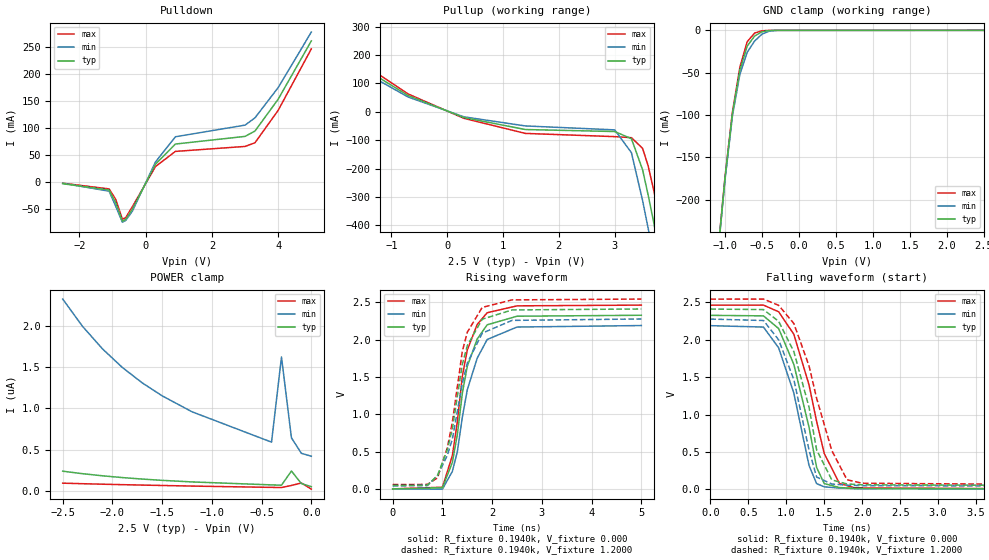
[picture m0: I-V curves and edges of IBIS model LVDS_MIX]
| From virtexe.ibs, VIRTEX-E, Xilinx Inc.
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|   Model LVDS_MIX
[Model]   LVDS_MIX
Model_type   I/O
Polarity   Non-Inverting
Enable   Active-Low
Vinh  = 1.4V
Vinl  = 1.0V
Vmeas =   1.2000V
Cref =  10.0000pF
Rref =   1.0000M
Vref =  0.000V
C_comp   5.0000pF   4.0000pF   6.0000pF
[Temperature Range]   85.0000   85.0000   85.0000
[Voltage Range]   2.5000V   2.3750V   2.6250V
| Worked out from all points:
|   slope of the pulldown table from 0 to 0.375 V, typ, clamps not added: 9.36 ohm
|   slope of the pullup table from 0 to 0.375 V, typ, clamps not added: 15.2 ohm
|   GND clamp passes 1 mA (typ) near -0.45 V on its own axis
|   rising waveform, R_fixture 0.1940k, V_fixture 0.000: 20-80 % time 389ps typ, 423ps min, 351ps max; typ from 0 V to 2.33 V
|   rising waveform, R_fixture 0.1940k, V_fixture 1.2000: 20-80 % time 417ps typ, 485ps min, 379ps max; typ from 0.048 V to 2.41 V
|   falling waveform, R_fixture 0.1940k, V_fixture 0.000: 20-80 % time 332ps typ, 319ps min, 365ps max; typ from 2.33 V to 0 V
|   falling waveform, R_fixture 0.1940k, V_fixture 1.2000: 20-80 % time 340ps typ, 332ps min, 422ps max; typ from 2.41 V to 0.048 V
[Pulldown]
| voltage   I(typ)   I(min)   I(max)
-2.5V     -3mA       -2mA       -2mA
-1.1V     -14.7mA    -16.9mA    -12.7mA
-900mV    -38.31mA   -45mA      -32.24mA
-700mV    -72.35mA   -74.44mA   -68.86mA
-600mV    -69.57mA   -71.16mA   -66.09mA
-400mV    -50.33mA   -54.17mA   -45.84mA
300mV     33.32mA    37.48mA    28.95mA
900mV     70.61mA    84.13mA    56.94mA
3V        84.79mA    105.7mA    66.17mA
3.3V      94.73mA    119.2mA    72.96mA
4V        153.8mA    175.4mA    133.2mA
5V        262mA      278.4mA    247.2mA
[Pullup]
| voltage   I(typ)   I(min)   I(max)
-2.5V     274.5mA    251.4mA    298.6mA
-700mV    57.48mA    52.2mA     62.97mA
300mV     -20.26mA   -17.68mA   -22.95mA
1.4V      -62.37mA   -49.71mA   -76.09mA
3V        -69.48mA   -63.59mA   -87.44mA
3.3V      -94.8mA    -144mA     -91.12mA
3.5V      -204.3mA   -312.7mA   -128.8mA
3.6V      -293.7mA   -410.9mA   -190.9mA
3.7V      -390.7mA   -512.3mA   -276.8mA
3.8V      -491.6mA   -615.7mA   -372.3mA
4V        -699.1mA   -826.2mA   -574.9mA
5V        -1.775A    -1.906A    -1.645A
[GND_clamp]
| voltage   I(typ)   I(min)   I(max)
-2.5V     -1.749A    -1.75A     -1.749A
-1.1V     -265.9mA   -267.2mA   -265mA
-1V       -174.2mA   -176mA     -172.9mA
-900mV    -98.19mA   -101.1mA   -96.16mA
-800mV    -47.11mA   -52.21mA   -43.56mA
-700mV    -18.56mA   -25.86mA   -13.33mA
-600mV    -6.793mA   -12.65mA   -3.234mA
-500mV    -1.657mA   -4.488mA   -550.9uA
-400mV    -239.6uA   -899.1uA   -68.76uA
-300mV    -25.6uA    -114.5uA   -6.558uA
2.5V      49.36nA    345.2nA    8.76nA
[POWER_clamp]
| voltage   I(typ)   I(min)   I(max)
-2.5V     237.1nA    2.325uA    91.79nA
-2.3V     206.5nA    1.993uA    85.16nA
-2.1V     181.1nA    1.721uA    79.1nA
-1.9V     159.5nA    1.495uA    73.57nA
-1.7V     141.4nA    1.308uA    68.39nA
-1.5V     125.8nA    1.151uA    63.62nA
-1.2V     106.8nA    957.8nA    56.46nA
-400mV    70.72nA    589.3nA    40.57nA
-300mV    66.88nA    1.623uA    38.88nA
-200mV    238.9nA    641.8nA    64.09nA
-100mV    86.32nA    454nA      93.77nA
0V        49.3nA     418.4nA    18.92nA
[Ramp]
| variable   typ   min   max
dV/dt_r   1.3968/0.3800n   1.3140/0.4175n   1.4782/0.3546n
dV/dt_f   1.4389/0.3829n   1.3728/0.3436n   1.5019/0.4619n
R_load = 0.1940k
[Rising Waveform]
R_fixture = 0.1940k
V_fixture = 0.000
| time   V(typ)   V(min)   V(max)
0s        46.06uV    676.3nV    272.9uV
1ns       15.54mV    -3.471mV   22.69mV
1.2ns     356.3mV    235.6mV    446.6mV
1.3ns     727.2mV    500.4mV    900.1mV
1.4ns     1.281V     959.5mV    1.509V
1.5ns     1.645V     1.329V     1.863V
1.7ns     2.01V      1.754V     2.205V
1.9ns     2.2V       2.003V     2.362V
2.5ns     2.315V     2.17V      2.454V
5ns       2.328V     2.19V      2.464V
[Rising Waveform]
R_fixture = 0.1940k
V_fixture = 1.2000
V_fixture_min = 1.1000
V_fixture_max = 1.3000
| time   V(typ)   V(min)   V(max)
0s        47.67mV    39.54mV    58.48mV
700ps     51.31mV    44.12mV    60.33mV
900ps     179mV      179.4mV    147.1mV
1.1ns     528.6mV    451.6mV    554.2mV
1.2ns     808.1mV    668.1mV    896mV
1.4ns     1.671V     1.417V     1.845V
1.5ns     1.921V     1.686V     2.1V
1.8ns     2.275V     2.088V     2.433V
2.4ns     2.399V     2.259V     2.534V
5ns       2.412V     2.278V     2.545V
[Falling Waveform]
R_fixture = 0.1940k
V_fixture = 0.000
| time   V(typ)   V(min)   V(max)
0s        2.328V     2.19V      2.464V
700ps     2.321V     2.171V     2.465V
900ps     2.151V     1.893V     2.376V
1.1ns     1.671V     1.286V     2.074V
1.3ns     830.5mV    317mV      1.397V
1.4ns     291.2mV    74.89mV    907.5mV
1.5ns     74.82mV    31.71mV    478.5mV
1.7ns     22.07mV    14.63mV    78.11mV
1.9ns     9.983mV    7.904mV    18.14mV
5ns       313.1uV    218.7uV    639.9uV
[Falling Waveform]
R_fixture = 0.1940k
V_fixture = 1.2000
V_fixture_min = 1.1000
V_fixture_max = 1.3000
| time   V(typ)   V(min)   V(max)
0s        2.412V     2.278V     2.545V
700ps     2.405V     2.259V     2.546V
900ps     2.248V     2V         2.462V
1.1ns     1.843V     1.468V     2.219V
1.3ns     1.098V     524mV      1.651V
1.4ns     526.6mV    162.7mV    1.217V
1.6ns     124.1mV    69.18mV    516.6mV
1.8ns     70.18mV    54.07mV    126.2mV
2ns       58.88mV    47.63mV    79.5mV
5ns       47.98mV    39.85mV    58.86mV
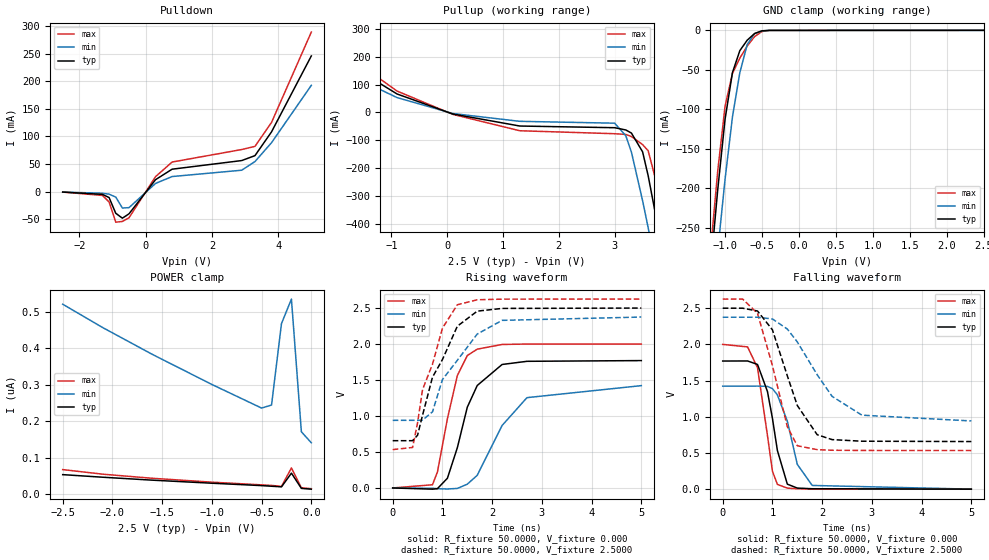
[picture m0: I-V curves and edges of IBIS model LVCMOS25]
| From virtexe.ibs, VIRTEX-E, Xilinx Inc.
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|   Model LVCMOS25
[Model]   LVCMOS25
Model_type   I/O
Polarity   Non-Inverting
Enable   Active-Low
Vinl =   0.800V
Vinh =   1.700V
Vmeas =   1.2500V
Cref =  35.0000pF
Rref =   1.0000M
Vref =  0.000V
C_comp   5.0000pF   4.0000pF   6.0000pF
[Temperature Range]   25.0000   100.0000   0.000
[Voltage Range]   2.5000V   2.3750V   2.6250V
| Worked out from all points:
|   slope of the pulldown table from 0 to 0.375 V, typ, clamps not added: 14.7 ohm
|   slope of the pullup table from 0 to 0.375 V, typ, clamps not added: 18.3 ohm
|   GND clamp passes 1 mA (typ) near -0.51 V on its own axis
|   rising waveform, R_fixture 50.0000, V_fixture 0.000: 20-80 % time 475ps typ, 726ps min, 366ps max; typ from 0 V to 1.77 V
|   rising waveform, R_fixture 50.0000, V_fixture 2.5000: 20-80 % time 601ps typ, 757ps min, 484ps max; typ from 0.657 V to 2.5 V
|   falling waveform, R_fixture 50.0000, V_fixture 0.000: 20-80 % time 280ps typ, 334ps min, 250ps max; typ from 1.77 V to 0 V
|   falling waveform, R_fixture 50.0000, V_fixture 2.5000: 20-80 % time 575ps typ, 866ps min, 429ps max; typ from 2.5 V to 0.658 V
[Pulldown]
| voltage   I(typ)   I(min)   I(max)
-2.5V     -1mA       -1mA       -1mA
-1.3V     -5.2mA     -3.1mA     -7.1mA
-1.1V     -11mA      -4.8mA     -19mA
-900mV    -39.41mA   -10.1mA    -55.57mA
-700mV    -48.31mA   -29.86mA   -54.19mA
-500mV    -40.4mA    -29.23mA   -47.55mA
300mV     21.42mA    14.64mA    26.88mA
800mV     40.44mA    27.11mA    53.39mA
2.9V      56.07mA    38.57mA    76.04mA
3.3V      64.99mA    54.26mA    81.79mA
3.8V      108.1mA    88.46mA    125.2mA
5V        245.6mA    192.3mA    288.8mA
[Pullup]
| voltage   I(typ)   I(min)   I(max)
-2.5V     264mA      205.8mA    306.3mA
-900mV    66.19mA    53.23mA    76.68mA
100mV     -5.905mA   -4.2mA     -7.259mA
1.3V      -49.08mA   -32.21mA   -66.08mA
3V        -55.16mA   -38.87mA   -76.74mA
3.2V      -63.29mA   -84.3mA    -79.31mA
3.3V      -74.42mA   -143mA     -86.88mA
3.5V      -141.8mA   -317.3mA   -115.8mA
3.6V      -227.8mA   -414.8mA   -137.9mA
3.8V      -437.8mA   -616.9mA   -292mA
4V        -661.8mA   -823.7mA   -513mA
5V        -1.826A    -1.883A    -1.708A
[GND_clamp]
| voltage   I(typ)   I(min)   I(max)
-2.5V     -1.803A    -1.736A    -1.828A
-1.2V     -306mA     -377.1mA   -282.7mA
-1.1V     -202.5mA   -280mA     -178.8mA
-1V       -112.5mA   -188.5mA   -95.98mA
-900mV    -53.49mA   -109.7mA   -54.53mA
-800mV    -25.67mA   -53.59mA   -35.13mA
-700mV    -12.44mA   -17.88mA   -19.82mA
-600mV    -3.982mA   -4.201mA   -7.865mA
-500mV    -601.5uA   -800.3uA   -1.508mA
-400mV    -51.05uA   -119.3uA   -124.3uA
2.5V      13.94nA    71.1nA     13.68nA
[POWER_clamp]
| voltage   I(typ)   I(min)   I(max)
-2.5V     53.73nA    520.7nA    67.52nA
-2.1V     46.68nA    457nA      55.06nA
-1.6V     38.59nA    383.4nA    43.77nA
-1V       30.21nA    300.8nA    33.12nA
-500mV    23.63nA    236.1nA    25.67nA
-400mV    21.94nA    244.4nA    24.16nA
-300mV    20.26nA    467.5nA    21.48nA
-200mV    57.86nA    534.8nA    72.06nA
-100mV    16.07nA    171.2nA    17.58nA
0V        13.91nA    140.9nA    15.19nA
[Ramp]
| variable   typ   min   max
dV/dt_r   1.0620/0.4714n   0.8532/0.7213n   1.2000/0.3582n
dV/dt_f   1.1053/0.5692n   0.8595/0.8591n   1.2547/0.4192n
R_load = 50.0000
[Rising Waveform]
R_fixture = 50.0000
V_fixture = 0.000
| time   V(typ)   V(min)   V(max)
0s        1.574uV    0V         1.467uV
800ps     -16.75mV   -4.734mV   44.61mV
900ps     -9.029mV   -10.48mV   223mV
1.1ns     134.9mV    -14.46mV   961.5mV
1.3ns     559.8mV    -6.614mV   1.562V
1.5ns     1.122V     52.66mV    1.84V
1.7ns     1.424V     175.5mV    1.929V
2.2ns     1.716V     868mV      1.994V
2.7ns     1.76V      1.255V     2V
5ns       1.77V      1.422V     2V
[Rising Waveform]
R_fixture = 50.0000
V_fixture = 2.5000
V_fixture_min = 2.3750
V_fixture_max = 2.6250
| time   V(typ)   V(min)   V(max)
0s        657mV      939.5mV    533.4mV
400ps     656.9mV    939.8mV    562.6mV
500ps     732.7mV    939.7mV    904.8mV
600ps     1.011V     942.6mV    1.367V
800ps     1.54V      1.058V     1.72V
1ns       1.784V     1.506V     2.22V
1.3ns     2.248V     1.774V     2.546V
1.7ns     2.457V     2.139V     2.615V
2.2ns     2.495V     2.329V     2.624V
5ns       2.5V       2.375V     2.625V
[Falling Waveform]
R_fixture = 50.0000
V_fixture = 0.000
| time   V(typ)   V(min)   V(max)
0s        1.77V      1.423V     2V
500ps     1.771V     1.423V     1.965V
700ps     1.723V     1.424V     1.678V
900ps     1.349V     1.42V      742.2mV
1ns       978.1mV    1.389V     247.6mV
1.1ns     533.6mV    1.302V     65.83mV
1.3ns     69.35mV    938.6mV    14.34mV
1.5ns     15.38mV    343.1mV    5.733mV
1.8ns     5.986mV    51.58mV    2.842mV
5ns       275.2uV    548.4uV    165.4uV
[Falling Waveform]
R_fixture = 50.0000
V_fixture = 2.5000
V_fixture_min = 2.3750
V_fixture_max = 2.6250
| time   V(typ)   V(min)   V(max)
0s        2.5V       2.375V     2.625V
400ps     2.5V       2.375V     2.626V
700ps     2.461V     2.375V     2.429V
1ns       2.201V     2.351V     1.706V
1.3ns     1.565V     2.212V     863.1mV
1.5ns     1.156V     2.034V     600.1mV
1.9ns     752.3mV    1.581V     546.1mV
2.2ns     684.7mV    1.282V     537.7mV
2.8ns     662.5mV    1.022V     534.8mV
5ns       657.8mV    942.5mV    533.8mV
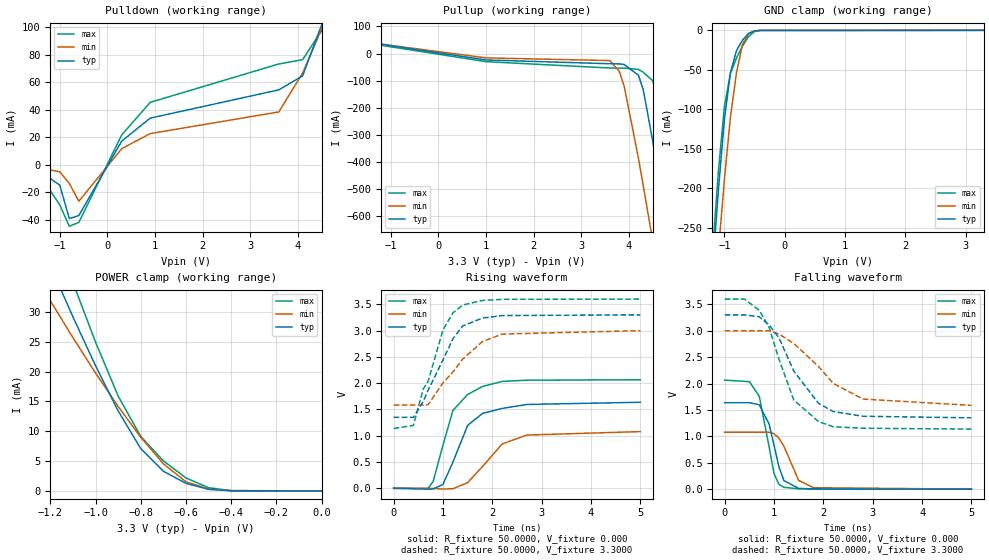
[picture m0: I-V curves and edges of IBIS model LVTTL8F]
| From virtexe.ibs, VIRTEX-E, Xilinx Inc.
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|   Model LVTTL8F
[Model]   LVTTL8F
Model_type   I/O
Polarity   Non-Inverting
Enable   Active-Low
Vinl =   0.800V
Vinh =   2.000V
Vmeas =   1.4000V
Cref =  35.0000pF
Rref =   1.0000M
Vref =  0.000V
C_comp   5.0000pF   4.0000pF   6.0000pF
[Temperature Range]   25.0000   100.0000   0.000
[Voltage Range]   3.3000V   3.0000V   3.6000V
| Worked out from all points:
|   slope of the pulldown table from 0 to 0.495 V, typ, clamps not added: 19.8 ohm
|   slope of the pullup table from 0 to 0.495 V, typ, clamps not added: 37.6 ohm
|   GND clamp passes 1 mA (typ) near -0.51 V on its own axis
|   POWER clamp passes 1 mA (typ) near -0.57 V on its own axis
|   rising waveform, R_fixture 50.0000, V_fixture 0.000: 20-80 % time 495ps typ, 625ps min, 454ps max; typ from 0 V to 1.64 V
|   rising waveform, R_fixture 50.0000, V_fixture 3.3000: 20-80 % time 610ps typ, 756ps min, 526ps max; typ from 1.35 V to 3.3 V
|   falling waveform, R_fixture 50.0000, V_fixture 0.000: 20-80 % time 268ps typ, 298ps min, 250ps max; typ from 1.64 V to 0 V
|   falling waveform, R_fixture 50.0000, V_fixture 3.3000: 20-80 % time 696ps typ, 988ps min, 566ps max; typ from 3.3 V to 1.35 V
[Pulldown]
| voltage   I(typ)   I(min)   I(max)
-3.3V     0A         -1mA       -1mA
-1.5V     -2.6mA     -1.7mA     -3.1mA
-1V       -14.7mA    -5mA       -29.02mA
-800mV    -38.95mA   -13.43mA   -44.46mA
-600mV    -36.69mA   -26.35mA   -41.68mA
300mV     17.27mA    11.77mA    21.73mA
900mV     33.93mA    22.71mA    45.37mA
3.6V      54.43mA    38.43mA    73.22mA
4.1V      64.55mA    66.63mA    76.35mA
4.5V      101.7mA    98.7mA     97.41mA
4.7V      124.3mA    116.2mA    121.3mA
6.6V      381.8mA    312.2mA    428.7mA
[Pullup]
| voltage   I(typ)   I(min)   I(max)
-3.3V     88.6mA     82.8mA     87.5mA
1V        -23.82mA   -16.13mA   -29.99mA
3.6V      -37.7mA    -26.02mA   -53.41mA
3.8V      -38.18mA   -66.39mA   -53.7mA
3.9V      -40.39mA   -120.1mA   -53.85mA
4.2V      -80.09mA   -385.5mA   -58.68mA
4.3V      -132.2mA   -485.2mA   -68.69mA
4.5V      -322.1mA   -689.5mA   -100.2mA
4.7V      -541.6mA   -897.5mA   -206mA
4.9V      -768.7mA   -1.107A    -417.4mA
5.1V      -999.4mA   -1.319A    -647.8mA
6.6V      -2.764A    -2.926A    -2.46A
[GND_clamp]
| voltage   I(typ)   I(min)   I(max)
-3.3V     -2.749A    -2.594A    -2.804A
-1.2V     -306mA     -377.1mA   -282.7mA
-1.1V     -202.5mA   -280mA     -178.8mA
-1V       -112.5mA   -188.5mA   -95.98mA
-900mV    -53.5mA    -109.7mA   -54.53mA
-800mV    -25.67mA   -53.59mA   -35.13mA
-700mV    -12.44mA   -17.88mA   -19.82mA
-600mV    -3.982mA   -4.202mA   -7.865mA
-500mV    -601.5uA   -800.3uA   -1.508mA
-400mV    -51.05uA   -119.3uA   -124.3uA
3.3V      18.74nA    3.634uA    18.92nA
[POWER_clamp]
| voltage   I(typ)   I(min)   I(max)
-3.3V     237mA      175.9mA    284.4mA
-1.3V     46.69mA    38.29mA    56.33mA
-1.2V     37.79mA    31.9mA     45.45mA
-1.1V     29.2mA     25.71mA    34.95mA
-1V       21.01mA    19.78mA    24.97mA
-900mV    13.43mA    14.17mA    15.91mA
-800mV    7.091mA    8.993mA    9.139mA
-700mV    3.305mA    4.554mA    5.052mA
-600mV    1.265mA    1.529mA    2.172mA
-500mV    263.8uA    333.6uA    531.5uA
-400mV    22.63uA    44.12uA    49.77uA
0V        18.8nA     38.36nA    22.53nA
[Ramp]
| variable   typ   min   max
dV/dt_r   0.9822/0.4911n   0.6474/0.6615n   1.2390/0.4610n
dV/dt_f   1.1694/0.6885n   0.8478/0.9605n   1.4772/0.5818n
R_load = 50.0000
[Rising Waveform]
R_fixture = 50.0000
V_fixture = 0.000
| time   V(typ)   V(min)   V(max)
0s        2.364uV    2.764uV    2.269uV
700ps     -16.3mV    -698.7uV   -272uV
800ps     -13.25mV   -4.005mV   129.4mV
1ns       74.85mV    -13.35mV   822.9mV
1.2ns     495.8mV    -8.334mV   1.48V
1.5ns     1.198V     108.3mV    1.785V
1.8ns     1.424V     414.5mV    1.938V
2.2ns     1.52V      844.5mV    2.033V
2.7ns     1.595V     1.013V     2.057V
5ns       1.637V     1.079V     2.065V
[Rising Waveform]
R_fixture = 50.0000
V_fixture = 3.3000
V_fixture_min = 3.0000
V_fixture_max = 3.6000
| time   V(typ)   V(min)   V(max)
0s        1.351V     1.585V     1.137V
400ps     1.349V     1.585V     1.197V
600ps     1.652V     1.583V     1.89V
700ps     1.871V     1.593V     2.039V
1ns       2.443V     2.006V     3.013V
1.2ns     2.843V     2.212V     3.336V
1.4ns     3.088V     2.458V     3.487V
1.8ns     3.239V     2.792V     3.573V
2.2ns     3.286V     2.934V     3.595V
5ns       3.3V       2.999V     3.6V
[Falling Waveform]
R_fixture = 50.0000
V_fixture = 0.000
| time   V(typ)   V(min)   V(max)
0s        1.637V     1.08V      2.065V
500ps     1.638V     1.08V      2.036V
700ps     1.598V     1.08V      1.762V
900ps     1.233V     1.078V     803.7mV
1ns       832.1mV    1.05V      292.3mV
1.1ns     421.6mV    966.4mV    92.28mV
1.2ns     163.9mV    814.7mV    35.1mV
1.5ns     14.58mV    164.3mV    6.546mV
1.8ns     5.759mV    28.14mV    3.148mV
5ns       304.3uV    347.7uV    258.4uV
[Falling Waveform]
R_fixture = 50.0000
V_fixture = 3.3000
V_fixture_min = 3.0000
V_fixture_max = 3.6000
| time   V(typ)   V(min)   V(max)
0s        3.3V       3V         3.6V
400ps     3.3V       3V         3.6V
700ps     3.264V     3V         3.388V
900ps     3.112V     2.998V     3.064V
1.1ns     2.865V     2.938V     2.462V
1.4ns     2.237V     2.76V      1.689V
1.9ns     1.627V     2.326V     1.28V
2.2ns     1.47V      2.003V     1.183V
2.8ns     1.381V     1.706V     1.154V
5ns       1.351V     1.587V     1.138V
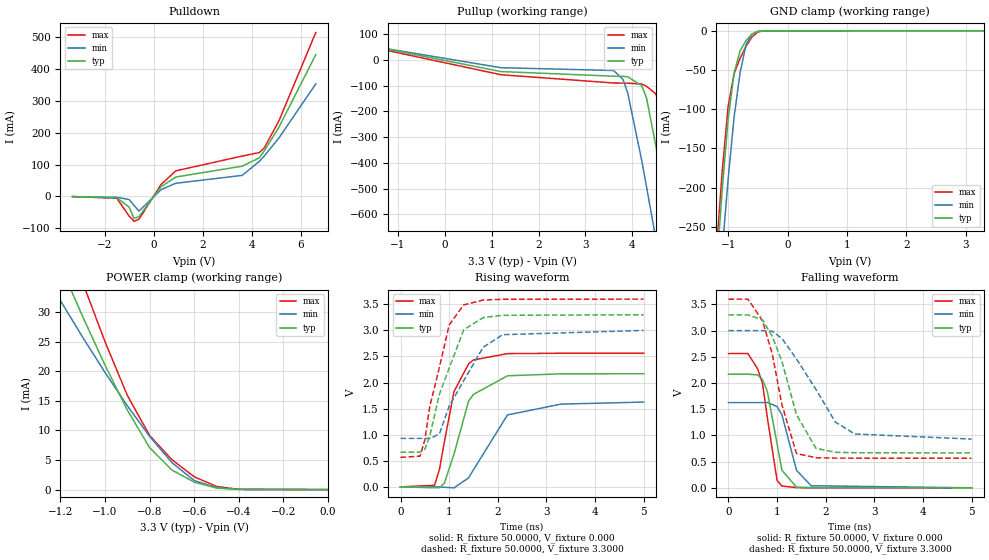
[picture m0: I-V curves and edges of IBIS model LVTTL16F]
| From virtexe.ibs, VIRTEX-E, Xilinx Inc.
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|   Model LVTTL16F
[Model]   LVTTL16F
Model_type   I/O
Polarity   Non-Inverting
Enable   Active-Low
Vinl =   0.800V
Vinh =   2.000V
Vmeas =   1.4000V
Cref =  35.0000pF
Rref =   1.0000M
Vref =  0.000V
C_comp   5.0000pF   4.0000pF   6.0000pF
[Temperature Range]   25.0000   100.0000   0.000
[Voltage Range]   3.3000V   3.0000V   3.6000V
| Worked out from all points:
|   slope of the pulldown table from 0 to 0.495 V, typ, clamps not added: 11.3 ohm
|   slope of the pullup table from 0 to 0.495 V, typ, clamps not added: 22.7 ohm
|   GND clamp passes 1 mA (typ) near -0.51 V on its own axis
|   POWER clamp passes 1 mA (typ) near -0.57 V on its own axis
|   rising waveform, R_fixture 50.0000, V_fixture 0.000: 20-80 % time 427ps typ, 615ps min, 363ps max; typ from 0 V to 2.17 V
|   rising waveform, R_fixture 50.0000, V_fixture 3.3000: 20-80 % time 515ps typ, 695ps min, 425ps max; typ from 0.665 V to 3.3 V
|   falling waveform, R_fixture 50.0000, V_fixture 0.000: 20-80 % time 257ps typ, 272ps min, 242ps max; typ from 2.17 V to 0 V
|   falling waveform, R_fixture 50.0000, V_fixture 3.3000: 20-80 % time 527ps typ, 807ps min, 422ps max; typ from 3.3 V to 0.666 V
[Pulldown]
| voltage   I(typ)   I(min)   I(max)
-3.3V     -1mA       -1mA       -1mA
-1.5V     -5mA       -3.3mA     -6.2mA
-1V       -33.9mA    -10.1mA    -62.22mA
-800mV    -70.04mA   -28.37mA   -78.77mA
-600mV    -63.86mA   -46.59mA   -72.41mA
300mV     29.85mA    20.7mA     36.95mA
900mV     60.59mA    40.95mA    80.02mA
3.6V      94.72mA    65.68mA    126.6mA
4.3V      120.9mA    109.5mA    137.7mA
4.5V      142.5mA    126.6mA    151.9mA
5.1V      217.4mA    183.5mA    237.3mA
6.6V      445.8mA    353.7mA    515.4mA
[Pullup]
| voltage   I(typ)   I(min)   I(max)
-3.3V     116.8mA    106.3mA    117.4mA
1.2V      -45.24mA   -30.27mA   -57.54mA
3.6V      -63.32mA   -41.14mA   -89.61mA
3.8V      -63.82mA   -75.74mA   -90.1mA
3.9V      -65.44mA   -127.4mA   -90.34mA
4.2V      -99.96mA   -391.3mA   -93.8mA
4.3V      -146.5mA   -490.9mA   -102.2mA
4.5V      -333.2mA   -695.1mA   -132.1mA
4.7V      -552mA     -903mA     -225.7mA
4.9V      -779mA     -1.113A    -433.5mA
5.1V      -1.009A    -1.324A    -663.2mA
6.6V      -2.775A    -2.931A    -2.475A
[GND_clamp]
| voltage   I(typ)   I(min)   I(max)
-3.3V     -2.749A    -2.594A    -2.805A
-1.2V     -306mA     -377.1mA   -282.7mA
-1.1V     -202.5mA   -280mA     -178.8mA
-1V       -112.5mA   -188.5mA   -95.98mA
-900mV    -53.5mA    -109.7mA   -54.53mA
-800mV    -25.67mA   -53.59mA   -35.13mA
-700mV    -12.44mA   -17.88mA   -19.82mA
-600mV    -3.982mA   -4.202mA   -7.866mA
-500mV    -601.5uA   -800.3uA   -1.508mA
-400mV    -51.05uA   -119.3uA   -124.5uA
3.3V      18.74nA    3.634uA    163.4nA
[POWER_clamp]
| voltage   I(typ)   I(min)   I(max)
-3.3V     237mA      175.9mA    284.4mA
-1.3V     46.69mA    38.29mA    56.33mA
-1.2V     37.79mA    31.9mA     45.45mA
-1.1V     29.2mA     25.71mA    34.95mA
-1V       21.01mA    19.78mA    24.97mA
-900mV    13.43mA    14.17mA    15.91mA
-800mV    7.091mA    8.993mA    9.139mA
-700mV    3.305mA    4.554mA    5.052mA
-600mV    1.265mA    1.529mA    2.172mA
-500mV    263.8uA    333.6uA    531.5uA
-400mV    22.63uA    44.12uA    49.77uA
0V        18.8nA     38.36nA    22.53nA
[Ramp]
| variable   typ   min   max
dV/dt_r   1.3014/0.4416n   0.9756/0.6118n   1.5372/0.3577n
dV/dt_f   1.5804/0.5476n   1.2415/0.8278n   1.8206/0.4171n
R_load = 50.0000
[Rising Waveform]
R_fixture = 50.0000
V_fixture = 0.000
| time   V(typ)   V(min)   V(max)
0s        1.652uV    1.922uV    1.601uV
700ps     -17.1mV    176.7uV    29.6mV
800ps     -17.24mV   -3.132mV   333.4mV
900ps     68.16mV    -7.704mV   854.8mV
1.1ns     629.3mV    -19.1mV    1.829V
1.4ns     1.647V     173.4mV    2.36V
1.5ns     1.773V     327.5mV    2.433V
2.2ns     2.13V      1.38V      2.555V
3.3ns     2.168V     1.587V     2.562V
5ns       2.169V     1.626V     2.562V
[Rising Waveform]
R_fixture = 50.0000
V_fixture = 3.3000
V_fixture_min = 3.0000
V_fixture_max = 3.6000
| time   V(typ)   V(min)   V(max)
0s        665.4mV    928.9mV    565.4mV
400ps     664.8mV    929.3mV    588.5mV
500ps     719.8mV    929.3mV    899.8mV
600ps     972.2mV    925.6mV    1.535V
800ps     1.776V     1.015V     2.293V
1ns       2.275V     1.547V     3.106V
1.3ns     3.013V     2.037V     3.49V
1.7ns     3.246V     2.678V     3.583V
2.1ns     3.29V      2.918V     3.597V
5ns       3.3V       3V         3.6V
[Falling Waveform]
R_fixture = 50.0000
V_fixture = 0.000
| time   V(typ)   V(min)   V(max)
0s        2.169V     1.627V     2.562V
400ps     2.169V     1.627V     2.563V
600ps     2.155V     1.627V     2.272V
700ps     2.067V     1.627V     1.992V
800ps     1.838V     1.629V     1.34V
1ns       843.3mV    1.552V     142.1mV
1.1ns     334.9mV    1.393V     35.03mV
1.4ns     13.5mV     335.1mV    4.991mV
1.7ns     4.548mV    40.84mV    2.221mV
5ns       129.4uV    363.8uV    191.5uV
[Falling Waveform]
R_fixture = 50.0000
V_fixture = 3.3000
V_fixture_min = 3.0000
V_fixture_max = 3.6000
| time   V(typ)   V(min)   V(max)
0s        3.3V       3V         3.6V
400ps     3.3V       3V         3.601V
700ps     3.206V     3V         3.192V
900ps     2.893V     2.989V     2.558V
1.1ns     2.414V     2.851V     1.584V
1.4ns     1.394V     2.458V     654mV
1.8ns     754.5mV    1.877V     575.5mV
2.2ns     678.8mV    1.254V     567.8mV
2.6ns     670.3mV    1.028V     566.6mV
5ns       666mV      930.8mV    565.7mV
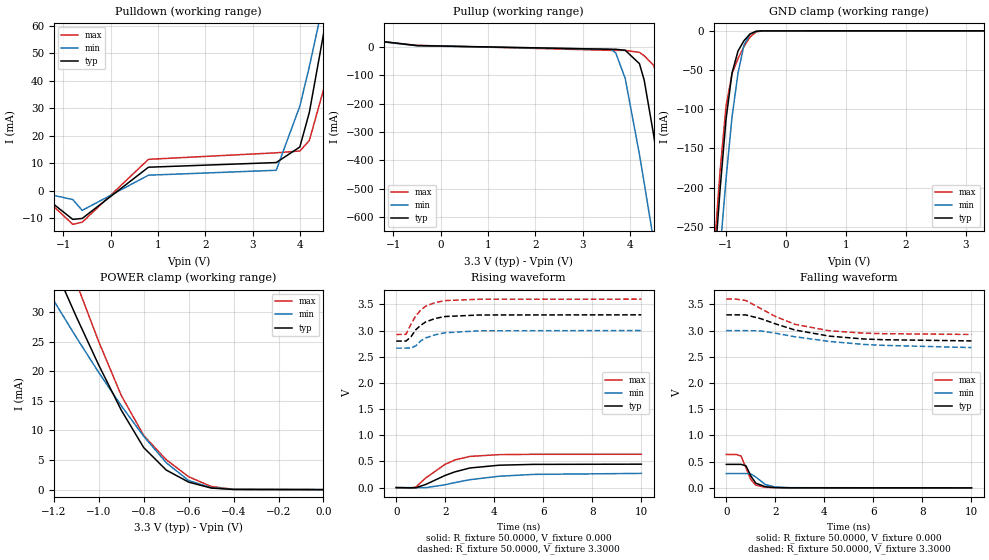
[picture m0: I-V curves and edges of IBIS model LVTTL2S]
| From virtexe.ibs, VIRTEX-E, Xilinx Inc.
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|   Model LVTTL2S
[Model]   LVTTL2S
Model_type   I/O
Polarity   Non-Inverting
Enable   Active-Low
Vinl =   0.800V
Vinh =   2.000V
Vmeas =   1.4000V
Cref =  35.0000pF
Rref =   1.0000M
Vref =  0.000V
C_comp   5.0000pF   4.0000pF   6.0000pF
[Temperature Range]   25.0000   100.0000   0.000
[Voltage Range]   3.3000V   3.0000V   3.6000V
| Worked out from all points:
|   slope of the pulldown table from 0 to 0.495 V, typ, clamps not added: 72.6 ohm
|   slope of the pullup table from 0 to 0.495 V, typ, clamps not added: 152 ohm
|   GND clamp passes 1 mA (typ) near -0.51 V on its own axis
|   POWER clamp passes 1 mA (typ) near -0.57 V on its own axis
|   rising waveform, R_fixture 50.0000, V_fixture 0.000: 20-80 % time 1.47ns typ, 2.2ns min, 1.21ns max; typ from 0 V to 0.448 V
|   rising waveform, R_fixture 50.0000, V_fixture 3.3000: 20-80 % time 780ps typ, 869ps min, 660ps max; typ from 2.8 V to 3.3 V
|   falling waveform, R_fixture 50.0000, V_fixture 0.000: 20-80 % time 339ps typ, 483ps min, 370ps max; typ from 0.448 V to 0 V
|   falling waveform, R_fixture 50.0000, V_fixture 3.3000: 20-80 % time 2.53ns typ, 3.31ns min, 2.17ns max; typ from 3.3 V to 2.8 V
[Pulldown]
| voltage   I(typ)   I(min)   I(max)
-3.3V     0A         0A         0A
-1.5V     -800uA     -500uA     -900uA
-800mV    -10.37mA   -3.16mA    -12.15mA
-600mV    -10.03mA   -7.098mA   -11.4mA
800mV     8.599mA    5.7mA      11.47mA
3.5V      10.29mA    7.484mA    13.84mA
4V        15.95mA    30.8mA     14.5mA
4.2V      28.48mA    45.11mA    18.27mA
4.5V      56.99mA    68.77mA    36.77mA
4.7V      78.21mA    85.56mA    59.04mA
4.9V      100.4mA    103mA      84.05mA
6.6V      305.2mA    264.8mA    320.6mA
[Pullup]
| voltage   I(typ)   I(min)   I(max)
-3.3V     57.9mA     57mA       55.1mA
-500mV    3.885mA    3.023mA    4.653mA
3.6V      -9.158mA   -9.435mA   -13.01mA
3.7V      -9.22mA    -22.12mA   -13.04mA
3.9V      -12.77mA   -112.2mA   -13.12mA
4.2V      -59.66mA   -379.1mA   -20.13mA
4.3V      -117.2mA   -478.9mA   -31.66mA
4.5V      -309.9mA   -683.4mA   -65.4mA
4.7V      -530mA     -891.4mA   -185.2mA
4.9V      -757.3mA   -1.101A    -399.7mA
5.1V      -988.1mA   -1.313A    -630.8mA
6.6V      -2.753A    -2.919A    -2.443A
[GND_clamp]
| voltage   I(typ)   I(min)   I(max)
-3.3V     -2.749A    -2.594A    -2.804A
-1.2V     -306mA     -377.1mA   -282.7mA
-1.1V     -202.5mA   -280mA     -178.8mA
-1V       -112.5mA   -188.5mA   -95.98mA
-900mV    -53.5mA    -109.7mA   -54.53mA
-800mV    -25.67mA   -53.59mA   -35.13mA
-700mV    -12.44mA   -17.88mA   -19.82mA
-600mV    -3.982mA   -4.202mA   -7.865mA
-500mV    -601.5uA   -800.3uA   -1.508mA
-400mV    -51.05uA   -119.3uA   -124.3uA
3.3V      18.74nA    3.634uA    18.92nA
[POWER_clamp]
| voltage   I(typ)   I(min)   I(max)
-3.3V     237mA      175.9mA    284.4mA
-1.3V     46.69mA    38.29mA    56.33mA
-1.2V     37.79mA    31.9mA     45.45mA
-1.1V     29.2mA     25.71mA    34.95mA
-1V       21.01mA    19.78mA    24.97mA
-900mV    13.43mA    14.17mA    15.91mA
-800mV    7.091mA    8.993mA    9.139mA
-700mV    3.305mA    4.554mA    5.052mA
-600mV    1.265mA    1.529mA    2.172mA
-500mV    263.8uA    333.6uA    531.5uA
-400mV    22.63uA    44.12uA    49.77uA
0V        18.8nA     38.3nA     22.53nA
[Ramp]
| variable   typ   min   max
dV/dt_r   0.2686/1.5061n   0.1628/2.2520n   0.3821/1.1512n
dV/dt_f   0.2982/2.5459n   0.1944/3.3756n   0.4044/2.1209n
R_load = 50.0000
[Rising Waveform]
R_fixture = 50.0000
V_fixture = 0.000
| time   V(typ)   V(min)   V(max)
0s        4.623uV    5.001uV    4.595uV
600ps     -4.323mV   -213.2uV   -5.002mV
800ps     -3.202mV   -2.826mV   10.53mV
1.2ns     59.38mV    -1.959mV   182.3mV
2ns       233.4mV    54.73mV    446.3mV
2.4ns     301.3mV    96.4mV     528.6mV
3ns       374.1mV    150.5mV    595.6mV
4.2ns     427.9mV    217.1mV    629.8mV
5.6ns     443.5mV    252.2mV    635.9mV
10ns      447.7mV    271.4mV    636.8mV
[Rising Waveform]
R_fixture = 50.0000
V_fixture = 3.3000
V_fixture_min = 3.0000
V_fixture_max = 3.6000
| time   V(typ)   V(min)   V(max)
0s        2.799V     2.664V     2.925V
400ps     2.799V     2.664V     2.928V
600ps     2.88V      2.667V     3.121V
800ps     3.016V     2.708V     3.283V
1ns       3.1V       2.803V     3.39V
1.2ns     3.164V     2.86V      3.466V
1.6ns     3.232V     2.92V      3.535V
2ns       3.268V     2.958V     3.572V
3.4ns     3.297V     2.995V     3.598V
10ns      3.3V       3V         3.6V
[Falling Waveform]
R_fixture = 50.0000
V_fixture = 0.000
| time   V(typ)   V(min)   V(max)
0s        447.8mV    272.6mV    636.8mV
400ps     447.8mV    272.6mV    636.9mV
600ps     447.9mV    272.6mV    607.8mV
800ps     420.5mV    272.8mV    382.4mV
1ns       226.1mV    266.6mV    157.7mV
1.2ns     90.23mV    205.9mV    51.77mV
1.6ns     20.52mV    61.28mV    9.863mV
2ns       4.827mV    15.28mV    2.716mV
2.6ns     1.226mV    3.226mV    740.4uV
10ns      24.85uV    50.11uV    26.57uV
[Falling Waveform]
R_fixture = 50.0000
V_fixture = 3.3000
V_fixture_min = 3.0000
V_fixture_max = 3.6000
| time   V(typ)   V(min)   V(max)
0s        3.3V       3V         3.6V
400ps     3.3V       3V         3.6V
800ps     3.298V     3V         3.574V
1.4ns     3.228V     2.994V     3.421V
2ns       3.129V     2.95V      3.269V
2.8ns     3.011V     2.882V     3.119V
4.2ns     2.894V     2.793V     2.997V
5.6ns     2.84V      2.736V     2.951V
6.4ns     2.826V     2.718V     2.941V
10ns      2.803V     2.676V     2.926V
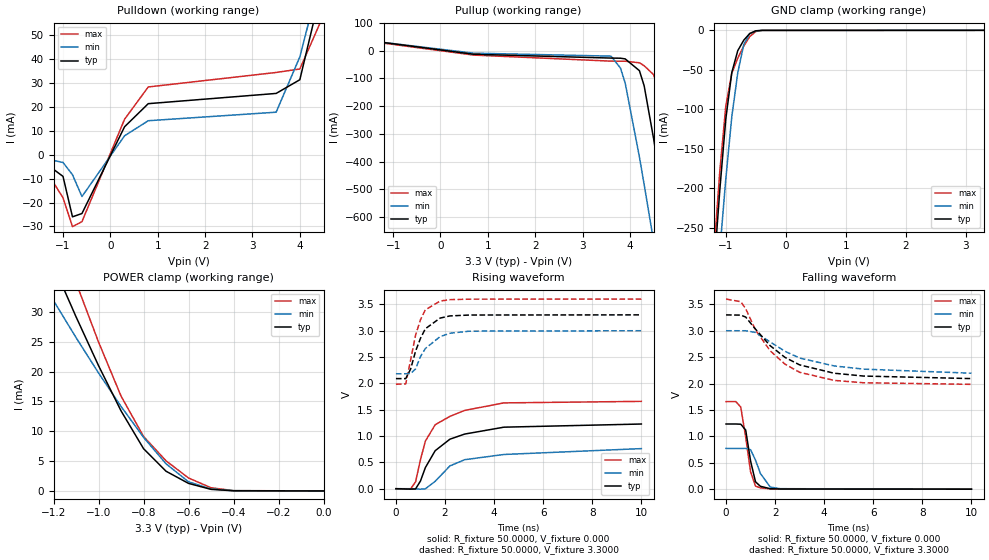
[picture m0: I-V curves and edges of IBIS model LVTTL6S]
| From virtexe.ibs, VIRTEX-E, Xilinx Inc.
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|   Model LVTTL6S
[Model]   LVTTL6S
Model_type   I/O
Polarity   Non-Inverting
Enable   Active-Low
Vinl =   0.800V
Vinh =   2.000V
Vmeas =   1.4000V
Cref =  35.0000pF
Rref =   1.0000M
Vref =  0.000V
C_comp   5.0000pF   4.0000pF   6.0000pF
[Temperature Range]   25.0000   100.0000   0.000
[Voltage Range]   3.3000V   3.0000V   3.6000V
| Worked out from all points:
|   slope of the pulldown table from 0 to 0.495 V, typ, clamps not added: 29.7 ohm
|   slope of the pullup table from 0 to 0.495 V, typ, clamps not added: 53.2 ohm
|   GND clamp passes 1 mA (typ) near -0.51 V on its own axis
|   POWER clamp passes 1 mA (typ) near -0.57 V on its own axis
|   rising waveform, R_fixture 50.0000, V_fixture 0.000: 20-80 % time 1.36ns typ, 2.06ns min, 1.03ns max; typ from 0 V to 1.23 V
|   rising waveform, R_fixture 50.0000, V_fixture 3.3000: 20-80 % time 614ps typ, 754ps min, 534ps max; typ from 2.09 V to 3.3 V
|   falling waveform, R_fixture 50.0000, V_fixture 0.000: 20-80 % time 300ps typ, 425ps min, 320ps max; typ from 1.23 V to 0 V
|   falling waveform, R_fixture 50.0000, V_fixture 3.3000: 20-80 % time 1.99ns typ, 2.5ns min, 1.67ns max; typ from 3.3 V to 2.09 V
[Pulldown]
| voltage   I(typ)   I(min)   I(max)
-3.3V     0A         -1mA       0A
-1.5V     -1.8mA     -1.2mA     -2.3mA
-1V       -9.1mA     -3.3mA     -18.02mA
-800mV    -25.98mA   -8.4mA     -30.06mA
-600mV    -24.59mA   -17.52mA   -28mA
300mV     11.6mA     7.84mA     14.73mA
800mV     21.23mA    14.11mA    28.2mA
3.5V      25.5mA     17.67mA    34.24mA
4V        31.21mA    40.72mA    35.7mA
4.5V      72.61mA    79.16mA    58.11mA
4.7V      94.42mA    96.24mA    81.09mA
6.6V      333.8mA    282.1mA    362.3mA
[Pullup]
| voltage   I(typ)   I(min)   I(max)
-3.3V     76.5mA     72.6mA     74.8mA
700mV     -12.61mA   -8.706mA   -15.61mA
3.6V      -26.42mA   -19.4mA    -37.49mA
3.8V      -26.91mA   -62.44mA   -37.69mA
3.9V      -29.44mA   -116.9mA   -37.79mA
4.2V      -71.79mA   -383mA     -43.41mA
4.3V      -126.2mA   -482.7mA   -54.06mA
4.5V      -317.3mA   -687.1mA   -86.33mA
4.7V      -537mA     -895.1mA   -197.6mA
4.9V      -764.2mA   -1.105A    -410.4mA
5.1V      -994.9mA   -1.316A    -641.1mA
6.6V      -2.76A     -2.923A    -2.453A
[GND_clamp]
| voltage   I(typ)   I(min)   I(max)
-3.3V     -2.749A    -2.594A    -2.805A
-1.2V     -306mA     -377.1mA   -282.7mA
-1.1V     -202.5mA   -280mA     -178.8mA
-1V       -112.5mA   -188.5mA   -95.98mA
-900mV    -53.5mA    -109.7mA   -54.53mA
-800mV    -25.67mA   -53.59mA   -35.13mA
-700mV    -12.44mA   -17.88mA   -19.82mA
-600mV    -3.982mA   -4.202mA   -7.865mA
-500mV    -601.5uA   -800.3uA   -1.508mA
-400mV    -51.05uA   -119.3uA   -124.3uA
3.3V      18.74nA    3.634uA    18.92nA
[POWER_clamp]
| voltage   I(typ)   I(min)   I(max)
-3.3V     237mA      175.9mA    284.4mA
-1.3V     46.69mA    38.29mA    56.33mA
-1.2V     37.79mA    31.9mA     45.45mA
-1.1V     29.2mA     25.71mA    34.95mA
-1V       21.01mA    19.78mA    24.97mA
-900mV    13.43mA    14.17mA    15.91mA
-800mV    7.091mA    8.993mA    9.139mA
-700mV    3.305mA    4.554mA    5.052mA
-600mV    1.265mA    1.529mA    2.172mA
-500mV    263.8uA    333.6uA    531.5uA
-400mV    22.63uA    44.12uA    49.77uA
0V        18.8nA     38.3nA     22.53nA
[Ramp]
| variable   typ   min   max
dV/dt_r   0.7368/1.3086n   0.4567/2.0552n   0.9948/0.9725n
dV/dt_f   0.7236/1.9477n   0.4824/2.5320n   0.9690/1.6177n
R_load = 50.0000
[Rising Waveform]
R_fixture = 50.0000
V_fixture = 0.000
| time   V(typ)   V(min)   V(max)
0s        2.858uV    3.293uV    2.756uV
600ps     -8.043mV   -173.9uV   -3.737mV
800ps     -4.719mV   -4.611mV   129.8mV
1ns       146.1mV    -8.809mV   550.7mV
1.2ns     401.1mV    -2.189mV   904.2mV
1.6ns     721.9mV    140.6mV    1.215V
2.2ns     940.1mV    432.6mV    1.373V
2.8ns     1.037V     550.4mV    1.486V
4.4ns     1.168V     649.7mV    1.629V
10ns      1.228V     761.1mV    1.658V
[Rising Waveform]
R_fixture = 50.0000
V_fixture = 3.3000
V_fixture_min = 3.0000
V_fixture_max = 3.6000
| time   V(typ)   V(min)   V(max)
0s        2.09V      2.182V     1.983V
400ps     2.09V      2.182V     1.99V
600ps     2.272V     2.187V     2.447V
800ps     2.61V      2.273V     2.913V
1ns       2.855V     2.507V     3.208V
1.2ns     3.037V     2.662V     3.396V
1.8ns     3.239V     2.887V     3.562V
2.2ns     3.28V      2.951V     3.589V
3ns       3.297V     2.991V     3.598V
10ns      3.3V       2.999V     3.6V
[Falling Waveform]
R_fixture = 50.0000
V_fixture = 0.000
| time   V(typ)   V(min)   V(max)
0s        1.234V     771.5mV    1.658V
400ps     1.234V     771.5mV    1.659V
600ps     1.23V      771.6mV    1.553V
800ps     1.12V      772.2mV    984mV
1ns       531.8mV    746.6mV    329mV
1.2ns     139.1mV    550mV      58.56mV
1.4ns     54.4mV     297.3mV    24.05mV
1.8ns     8.62mV     40.52mV    5.529mV
2.2ns     3.478mV    9.107mV    2.45mV
10ns      159uV      72.88uV    130.6uV
[Falling Waveform]
R_fixture = 50.0000
V_fixture = 3.3000
V_fixture_min = 3.0000
V_fixture_max = 3.6000
| time   V(typ)   V(min)   V(max)
0s        3.3V       3V         3.6V
600ps     3.296V     3V         3.55V
800ps     3.259V     3V         3.418V
1.2ns     3.03V      2.968V     3.013V
1.8ns     2.716V     2.787V     2.619V
2.4ns     2.496V     2.611V     2.368V
3ns       2.353V     2.483V     2.213V
4.4ns     2.196V     2.334V     2.06V
5.6ns     2.142V     2.273V     2.015V
10ns      2.094V     2.196V     1.985V
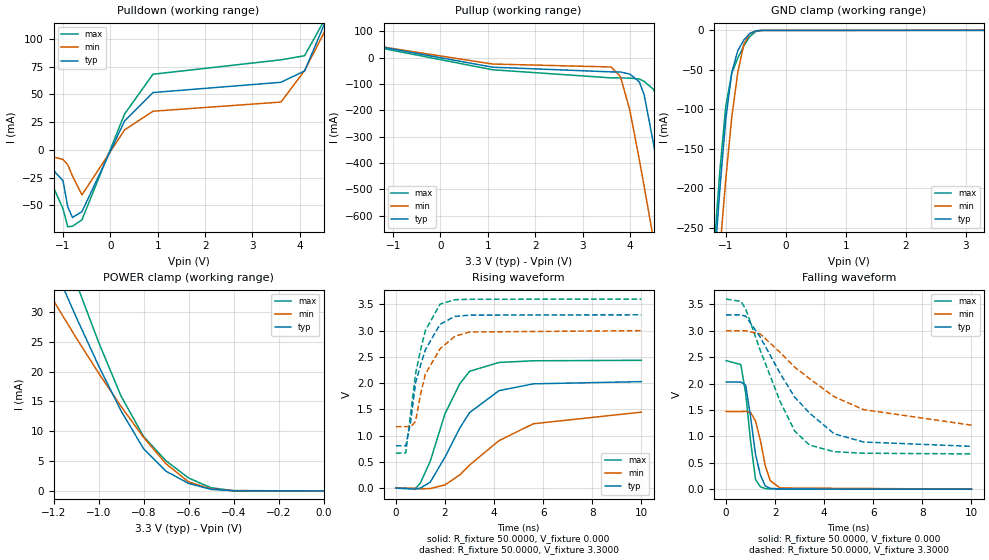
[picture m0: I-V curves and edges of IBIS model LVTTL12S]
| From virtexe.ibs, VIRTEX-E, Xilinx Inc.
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|   Model LVTTL12S
[Model]   LVTTL12S
Model_type   I/O
Polarity   Non-Inverting
Enable   Active-Low
Vinl =   0.800V
Vinh =   2.000V
Vmeas =   1.4000V
Cref =  35.0000pF
Rref =   1.0000M
Vref =  0.000V
C_comp   5.0000pF   4.0000pF   6.0000pF
[Temperature Range]   25.0000   100.0000   0.000
[Voltage Range]   3.3000V   3.0000V   3.6000V
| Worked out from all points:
|   slope of the pulldown table from 0 to 0.495 V, typ, clamps not added: 13 ohm
|   slope of the pullup table from 0 to 0.495 V, typ, clamps not added: 26.2 ohm
|   GND clamp passes 1 mA (typ) near -0.51 V on its own axis
|   POWER clamp passes 1 mA (typ) near -0.57 V on its own axis
|   rising waveform, R_fixture 50.0000, V_fixture 0.000: 20-80 % time 1.71ns typ, 2.58ns min, 1.18ns max; typ from 0 V to 2.03 V
|   rising waveform, R_fixture 50.0000, V_fixture 3.3000: 20-80 % time 778ps typ, 865ps min, 658ps max; typ from 0.807 V to 3.3 V
|   falling waveform, R_fixture 50.0000, V_fixture 0.000: 20-80 % time 415ps typ, 444ps min, 365ps max; typ from 2.03 V to 0 V
|   falling waveform, R_fixture 50.0000, V_fixture 3.3000: 20-80 % time 2.22ns typ, 3.22ns min, 1.56ns max; typ from 3.3 V to 0.811 V
[Pulldown]
| voltage   I(typ)   I(min)   I(max)
-3.3V     -1mA       -1mA       0A
-1.5V     -4.4mA     -2.9mA     -5.5mA
-1V       -27.7mA    -8.6mA     -52.82mA
-900mV    -51.1mA    -13.3mA    -69.17mA
-800mV    -60.81mA   -23.53mA   -68.67mA
-600mV    -55.52mA   -40.47mA   -62.88mA
300mV     26mA       18mA       32.25mA
900mV     51.58mA    34.76mA    68.05mA
3.6V      60.8mA     43.02mA    80.99mA
4.1V      70.96mA    71.17mA    84.69mA
4.7V      131.3mA    121.1mA    130.5mA
6.6V      394.5mA    320.2mA    447mA
[Pullup]
| voltage   I(typ)   I(min)   I(max)
-3.3V     107.1mA    98.2mA     107.1mA
1.1V      -36.77mA   -24.77mA   -46.5mA
3.6V      -54.57mA   -35.94mA   -77.25mA
3.8V      -55.05mA   -72.48mA   -77.68mA
4V        -63.12mA   -202mA     -78.1mA
4.2V      -93.01mA   -389.3mA   -81.74mA
4.3V      -141.5mA   -489mA     -90.74mA
4.5V      -329.4mA   -693.2mA   -121.1mA
4.7V      -548.5mA   -901.1mA   -218.8mA
4.9V      -775.5mA   -1.111A    -428mA
5.1V      -1.006A    -1.322A    -657.9mA
6.6V      -2.771A    -2.929A    -2.47A
[GND_clamp]
| voltage   I(typ)   I(min)   I(max)
-3.3V     -2.749A    -2.594A    -2.805A
-1.2V     -306mA     -377.1mA   -282.7mA
-1.1V     -202.5mA   -280mA     -178.8mA
-1V       -112.5mA   -188.5mA   -95.98mA
-900mV    -53.5mA    -109.7mA   -54.53mA
-800mV    -25.67mA   -53.59mA   -35.13mA
-700mV    -12.44mA   -17.88mA   -19.82mA
-600mV    -3.982mA   -4.202mA   -7.865mA
-500mV    -601.5uA   -800.3uA   -1.508mA
-400mV    -51.05uA   -119.3uA   -124.3uA
3.3V      18.74nA    3.634uA    18.92nA
[POWER_clamp]
| voltage   I(typ)   I(min)   I(max)
-3.3V     237mA      175.9mA    284.4mA
-1.3V     46.69mA    38.29mA    56.33mA
-1.2V     37.79mA    31.9mA     45.45mA
-1.1V     29.2mA     25.71mA    34.95mA
-1V       21.01mA    19.78mA    24.97mA
-900mV    13.43mA    14.17mA    15.91mA
-800mV    7.091mA    8.993mA    9.139mA
-700mV    3.305mA    4.554mA    5.052mA
-600mV    1.265mA    1.529mA    2.172mA
-500mV    263.8uA    333.6uA    531.5uA
-400mV    22.63uA    44.12uA    49.77uA
0V        18.8nA     38.3nA     22.53nA
[Ramp]
| variable   typ   min   max
dV/dt_r   1.2168/1.7068n   0.8682/2.5678n   1.4604/1.1702n
dV/dt_f   1.4933/2.2209n   1.0728/3.2486n   1.7594/1.5229n
R_load = 50.0000
[Rising Waveform]
R_fixture = 50.0000
V_fixture = 0.000
| time   V(typ)   V(min)   V(max)
0s        1.707uV    1.983uV    1.656uV
800ps     -19.65mV   -4.211mV   -6.921mV
1ns       1.562mV    -14.21mV   100.5mV
1.4ns     114mV      -7.907mV   514.8mV
2ns       591.6mV    61.37mV    1.419V
2.6ns     1.142V     252.6mV    1.984V
3ns       1.438V     439.3mV    2.224V
4.2ns     1.856V     904.7mV    2.393V
5.6ns     1.986V     1.226V     2.425V
10ns      2.028V     1.447V     2.434V
[Rising Waveform]
R_fixture = 50.0000
V_fixture = 3.3000
V_fixture_min = 3.0000
V_fixture_max = 3.6000
| time   V(typ)   V(min)   V(max)
0s        807.3mV    1.17V      667mV
400ps     805.8mV    1.17V      669.3mV
600ps     1.262V     1.169V     1.429V
800ps     1.999V     1.269V     2.179V
1ns       2.334V     1.777V     2.625V
1.2ns     2.635V     2.171V     3.001V
1.8ns     3.119V     2.654V     3.504V
2.4ns     3.27V      2.89V      3.588V
3ns       3.294V     2.973V     3.596V
10ns      3.3V       2.999V     3.6V
[Falling Waveform]
R_fixture = 50.0000
V_fixture = 0.000
| time   V(typ)   V(min)   V(max)
0s        2.03V      1.471V     2.434V
600ps     2.029V     1.471V     2.361V
800ps     1.968V     1.472V     1.814V
1ns       1.368V     1.456V     910.2mV
1.2ns     659.8mV    1.29V      184.9mV
1.4ns     267.5mV    921.5mV    44.01mV
1.6ns     59.55mV    441.7mV    11.29mV
1.8ns     16.02mV    162.7mV    5.785mV
2.2ns     4.766mV    22.64mV    2.43mV
10ns      78.1uV     191.8uV    46.34uV
[Falling Waveform]
R_fixture = 50.0000
V_fixture = 3.3000
V_fixture_min = 3.0000
V_fixture_max = 3.6000
| time   V(typ)   V(min)   V(max)
0s        3.3V       3V         3.6V
600ps     3.3V       3V         3.556V
800ps     3.275V     3V         3.414V
1.4ns     2.875V     2.938V     2.622V
2.2ns     2.195V     2.59V      1.663V
2.8ns     1.74V      2.309V     1.099V
3.4ns     1.442V     2.094V     835.2mV
4.4ns     1.05V      1.752V     709.5mV
5.6ns     893.3mV    1.507V     680.8mV
10ns      811.2mV    1.212V     667.6mV
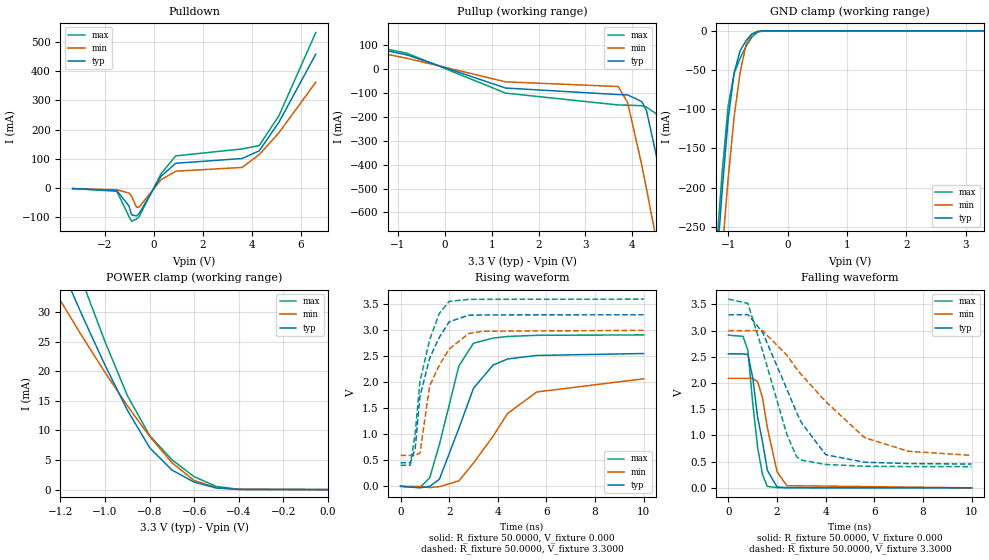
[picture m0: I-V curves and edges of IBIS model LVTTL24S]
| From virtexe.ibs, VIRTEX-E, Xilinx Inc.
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|   Model LVTTL24S
[Model]   LVTTL24S
Model_type   I/O
Polarity   Non-Inverting
Enable   Active-Low
Vinl =   0.800V
Vinh =   2.000V
Vmeas =   1.4000V
Cref =  35.0000pF
Rref =   1.0000M
Vref =  0.000V
C_comp   5.0000pF   4.0000pF   6.0000pF
[Temperature Range]   25.0000   100.0000   0.000
[Voltage Range]   3.3000V   3.0000V   3.6000V
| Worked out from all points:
|   slope of the pulldown table from 0 to 0.495 V, typ, clamps not added: 8.13 ohm
|   slope of the pullup table from 0 to 0.495 V, typ, clamps not added: 13.9 ohm
|   GND clamp passes 1 mA (typ) near -0.51 V on its own axis
|   POWER clamp passes 1 mA (typ) near -0.57 V on its own axis
|   rising waveform, R_fixture 50.0000, V_fixture 0.000: 20-80 % time 1.28ns typ, 2.19ns min, 925ps max; typ from 0 V to 2.55 V
|   rising waveform, R_fixture 50.0000, V_fixture 3.3000: 20-80 % time 808ps typ, 870ps min, 706ps max; typ from 0.452 V to 3.3 V
|   falling waveform, R_fixture 50.0000, V_fixture 0.000: 20-80 % time 521ps typ, 521ps min, 415ps max; typ from 2.56 V to 0 V
|   falling waveform, R_fixture 50.0000, V_fixture 3.3000: 20-80 % time 1.67ns typ, 2.84ns min, 1.23ns max; typ from 3.3 V to 0.454 V
[Pulldown]
| voltage   I(typ)   I(min)   I(max)
-3.3V     -1mA       -2mA       -1mA
-1.5V     -8.1mA     -5.1mA     -10.3mA
-1V       -61.1mA    -16.7mA    -97.52mA
-900mV    -90.9mA    -27mA      -113mA
-700mV    -94.96mA   -64.61mA   -105.3mA
-600mV    -87.5mA    -65.07mA   -98.53mA
300mV     40.88mA    28.97mA    49.64mA
900mV     85.36mA    58.31mA    110.6mA
3.6V      101.6mA    71.07mA    134.3mA
4.3V      128mA      114.9mA    146.1mA
5.1V      225.6mA    189.5mA    247.7mA
6.6V      458.1mA    362.2mA    532.1mA
[Pullup]
| voltage   I(typ)   I(min)   I(max)
-3.3V     164mA      145.7mA    167.3mA
-800mV    59.77mA    45.78mA    67.04mA
1.3V      -78.71mA   -52.7mA    -99.97mA
3.7V      -106.1mA   -72.4mA    -149.7mA
3.9V      -107.5mA   -140.1mA   -150.5mA
4.2V      -135.5mA   -401.1mA   -152.8mA
4.3V      -172.4mA   -500.5mA   -158.4mA
4.5V      -352mA     -704.4mA   -185.3mA
4.7V      -569.5mA   -912.2mA   -261.9mA
4.9V      -796mA     -1.122A    -460.6mA
5.1V      -1.026A    -1.333A    -688.6mA
6.6V      -2.792A    -2.941A    -2.5A
[GND_clamp]
| voltage   I(typ)   I(min)   I(max)
-3.3V     -2.749A    -2.594A    -2.805A
-1.2V     -306mA     -377.1mA   -282.7mA
-1.1V     -202.5mA   -280mA     -178.8mA
-1V       -112.5mA   -188.5mA   -95.98mA
-900mV    -53.5mA    -109.7mA   -54.53mA
-800mV    -25.67mA   -53.59mA   -35.13mA
-700mV    -12.44mA   -17.88mA   -19.82mA
-600mV    -3.982mA   -4.202mA   -7.866mA
-500mV    -601.5uA   -800.3uA   -1.508mA
-400mV    -51.05uA   -119.3uA   -124.5uA
3.3V      18.74nA    3.634uA    163.4nA
[POWER_clamp]
| voltage   I(typ)   I(min)   I(max)
-3.3V     237mA      175.9mA    284.4mA
-1.3V     46.69mA    38.29mA    56.33mA
-1.2V     37.79mA    31.9mA     45.45mA
-1.1V     29.2mA     25.71mA    34.95mA
-1V       21.01mA    19.78mA    24.97mA
-900mV    13.43mA    14.17mA    15.91mA
-800mV    7.091mA    8.993mA    9.139mA
-700mV    3.305mA    4.554mA    5.052mA
-600mV    1.265mA    1.529mA    2.172mA
-500mV    263.8uA    333.6uA    531.5uA
-400mV    22.63uA    44.12uA    49.77uA
0V        18.8nA     38.36nA    22.53nA
[Ramp]
| variable   typ   min   max
dV/dt_r   1.5324/1.2682n   1.2408/2.1324n   1.7472/0.9177n
dV/dt_f   1.7075/1.6653n   1.4281/2.8436n   1.9176/1.1764n
R_load = 50.0000
[Rising Waveform]
R_fixture = 50.0000
V_fixture = 0.000
| time   V(typ)   V(min)   V(max)
0s        1.278uV    1.453uV    1.262uV
800ps     -29.7mV    -3.161mV   -22.26mV
1.2ns     -1.666mV   -24.37mV   165.3mV
1.6ns     137.5mV    -6.794mV   806.6mV
2.4ns     1.116V     104.6mV    2.314V
3ns       1.885V     447.3mV    2.752V
3.8ns     2.329V     958.4mV    2.85V
4.4ns     2.449V     1.399V     2.882V
5.6ns     2.517V     1.814V     2.904V
10ns      2.554V     2.068V     2.912V
[Rising Waveform]
R_fixture = 50.0000
V_fixture = 3.3000
V_fixture_min = 3.0000
V_fixture_max = 3.6000
| time   V(typ)   V(min)   V(max)
0s        452.1mV    594mV      403.5mV
400ps     452.4mV    594.1mV    405.5mV
600ps     718.3mV    593.9mV    1.002V
800ps     1.728V     639.2mV    2.015V
1.2ns     2.469V     1.934V     2.823V
1.6ns     2.869V     2.333V     3.329V
2ns       3.163V     2.638V     3.556V
2.8ns     3.291V     2.938V     3.595V
3.4ns     3.296V     2.983V     3.596V
10ns      3.299V     2.999V     3.6V
[Falling Waveform]
R_fixture = 50.0000
V_fixture = 0.000
| time   V(typ)   V(min)   V(max)
0s        2.555V     2.089V     2.912V
600ps     2.556V     2.089V     2.89V
800ps     2.545V     2.089V     2.623V
1ns       2.099V     2.088V     1.61V
1.2ns     1.345V     2.025V     769.6mV
1.4ns     882.1mV    1.721V     255.2mV
1.6ns     334.1mV    1.148V     27.56mV
2ns       16.55mV    307.5mV    4.407mV
2.4ns     4.397mV    41.62mV    2.047mV
10ns      132.9uV    179.4uV    -72.59uV
[Falling Waveform]
R_fixture = 50.0000
V_fixture = 3.3000
V_fixture_min = 3.0000
V_fixture_max = 3.6000
| time   V(typ)   V(min)   V(max)
0s        3.3V       3V         3.6V
800ps     3.304V     3V         3.518V
1.4ns     2.969V     3.001V     2.62V
2.4ns     1.886V     2.533V     1.024V
2.8ns     1.438V     2.273V     595mV
3ns       1.245V     2.158V     529.3mV
4ns       632.2mV    1.645V     445.6mV
5.6ns     488.9mV    957.9mV    413mV
7.4ns     463mV      697.4mV    405.9mV
10ns      454.2mV    619.9mV    404mV
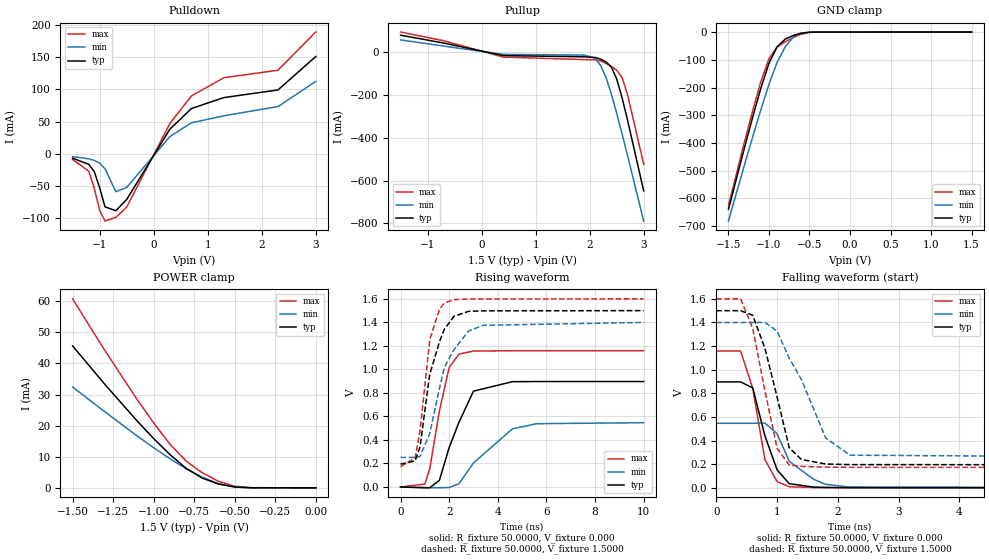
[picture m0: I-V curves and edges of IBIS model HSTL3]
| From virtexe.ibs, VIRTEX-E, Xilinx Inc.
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|   Model HSTL3
[Model]   HSTL3
Model_type   I/O
Polarity   Non-Inverting
Enable   Active-Low
Vinl =   0.800V
Vinh =   1.000V
Vmeas =   0.9000V
Cref =  20.0000pF
Rref =  50.0000
Vref =   1.5000V
C_comp   5.0000pF   4.0000pF   6.0000pF
[Temperature Range]   25.0000   100.0000   0.000
[Voltage Range]   1.5000V   1.4000V   1.6000V
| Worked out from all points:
|   slope of the pulldown table from 0 to 0.225 V, typ, clamps not added: 7.58 ohm
|   slope of the pullup table from 0 to 0.225 V, typ, clamps not added: 23.5 ohm
|   GND clamp passes 1 mA (typ) near -0.51 V on its own axis
|   POWER clamp passes 1 mA (typ) near -0.58 V on its own axis
|   rising waveform, R_fixture 50.0000, V_fixture 0.000: 20-80 % time 928ps typ, 1.47ns min, 624ps max; typ from 0 V to 0.897 V
|   rising waveform, R_fixture 50.0000, V_fixture 1.5000: 20-80 % time 728ps typ, 971ps min, 506ps max; typ from 0.194 V to 1.5 V
|   falling waveform, R_fixture 50.0000, V_fixture 0.000: 20-80 % time 318ps typ, 467ps min, 261ps max; typ from 0.897 V to 0 V
|   falling waveform, R_fixture 50.0000, V_fixture 1.5000: 20-80 % time 387ps typ, 617ps min, 337ps max; typ from 1.5 V to 0.194 V
[Pulldown]
| voltage   I(typ)   I(min)   I(max)
-1.5V     -7mA       -4.5mA     -8.8mA
-1.2V     -16.5mA    -7.9mA     -27.3mA
-1.1V     -27.6mA    -10.3mA    -53.1mA
-1V       -52.8mA    -14.5mA    -88.03mA
-900mV    -82.61mA   -23.4mA    -104.6mA
-700mV    -88.57mA   -59.02mA   -98.89mA
-500mV    -71.28mA   -52.46mA   -83.02mA
300mV     38.22mA    26.69mA    47mA
700mV     70.27mA    48.08mA    89.88mA
1.3V      87.31mA    59.03mA    118.2mA
2.3V      99.13mA    73.31mA    129.8mA
3V        151.1mA    112.4mA    189.2mA
[Pullup]
| voltage   I(typ)   I(min)   I(max)
-1.5V     80.99mA    58.81mA    95.66mA
-700mV    43.92mA    29.88mA    54.7mA
400mV     -14.75mA   -8.945mA   -21.71mA
1.9V      -20.46mA   -12.26mA   -33.54mA
2.1V      -23.68mA   -26.88mA   -34.7mA
2.2V      -31.41mA   -60.03mA   -39.61mA
2.3V      -43.82mA   -115mA     -50.52mA
2.4V      -67.75mA   -193.4mA   -65.34mA
2.5V      -123.4mA   -284.7mA   -83.26mA
2.6V      -212.2mA   -381.6mA   -117.7mA
2.7V      -315.2mA   -481.5mA   -196.1mA
3V        -648.4mA   -789.7mA   -524mA
[GND_clamp]
| voltage   I(typ)   I(min)   I(max)
-1.5V     -639.4mA   -681.4mA   -625.3mA
-1.3V     -414.8mA   -476.9mA   -394mA
-1.2V     -306mA     -377mA     -282.7mA
-1.1V     -202.5mA   -280mA     -178.7mA
-1V       -112.5mA   -188.5mA   -95.97mA
-900mV    -53.49mA   -109.7mA   -54.51mA
-800mV    -25.66mA   -53.59mA   -35.12mA
-700mV    -12.43mA   -17.88mA   -19.81mA
-600mV    -3.981mA   -4.201mA   -7.863mA
-500mV    -601.5uA   -800.2uA   -1.508mA
-400mV    -51.04uA   -119.3uA   -124.3uA
1.5V      8.586nA    31.4nA     8.324nA
[POWER_clamp]
| voltage   I(typ)   I(min)   I(max)
-1.5V     45.61mA    32.41mA    60.74mA
-1.3V     33.2mA     24.4mA     44.06mA
-1.1V     21.39mA    16.59mA    28.25mA
-1V       15.85mA    12.89mA    20.86mA
-900mV    10.72mA    9.386mA    14.08mA
-800mV    6.271mA    6.174mA    8.616mA
-700mV    3.136mA    3.398mA    4.838mA
-600mV    1.222mA    1.343mA    2.099mA
-500mV    258.2uA    323.8uA    517.7uA
-400mV    22.21uA    43.58uA    48.44uA
0V        8.586nA    20.17nA    9.284nA
[Ramp]
| variable   typ   min   max
dV/dt_r   0.5383/0.9497n   0.3280/1.4611n   0.6954/0.5796n
dV/dt_f   0.7835/0.3725n   0.6892/0.5483n   0.8564/0.3057n
R_load = 50.0000
[Rising Waveform]
R_fixture = 50.0000
V_fixture = 0.000
| time   V(typ)   V(min)   V(max)
0s        0V         0V         0V
1ns       -7.339mV   -3.991mV   25.02mV
1.2ns     -6.881mV   -5.682mV   153.6mV
1.6ns     57.2mV     -6.629mV   648mV
2ns       335.4mV    -4.189mV   1.016V
2.4ns     548.7mV    27.25mV    1.13V
3ns       815.2mV    203.9mV    1.156V
4.6ns     895.5mV    494.2mV    1.159V
5.6ns     896.9mV    538.3mV    1.159V
10ns      897.1mV    546.7mV    1.159V
[Rising Waveform]
R_fixture = 50.0000
V_fixture = 1.5000
V_fixture_min = 1.4000
V_fixture_max = 1.6000
| time   V(typ)   V(min)   V(max)
0s        194.1mV    251.2mV    172.5mV
600ps     222.2mV    251.8mV    245.5mV
800ps     338.5mV    259.2mV    474.1mV
1.2ns     956.8mV    454.2mV    1.25V
1.6ns     1.234V     838.5mV    1.51V
1.8ns     1.341V     1.016V     1.565V
2.2ns     1.452V     1.169V     1.594V
2.8ns     1.494V     1.327V     1.599V
3.4ns     1.498V     1.375V     1.599V
10ns      1.5V       1.4V       1.6V
[Falling Waveform]
R_fixture = 50.0000
V_fixture = 0.000
| time   V(typ)   V(min)   V(max)
0s        897.1mV    546.7mV    1.159V
400ps     897.1mV    546.7mV    1.159V
600ps     845.8mV    546.7mV    840.9mV
800ps     440.4mV    548.9mV    238.4mV
1ns       152.7mV    458.1mV    52.87mV
1.2ns     35.44mV    225mV      9.504mV
1.6ns     6.322mV    72.14mV    2.695mV
1.8ns     3.625mV    29.8mV     1.602mV
2.2ns     1.518mV    7.277mV    758.8uV
10ns      71.99uV    132.4uV    50.24uV
[Falling Waveform]
R_fixture = 50.0000
V_fixture = 1.5000
V_fixture_min = 1.4000
V_fixture_max = 1.6000
| time   V(typ)   V(min)   V(max)
0s        1.5V       1.4V       1.6V
400ps     1.5V       1.4V       1.6V
600ps     1.461V     1.4V       1.35V
800ps     1.182V     1.401V     822.2mV
1ns       770mV      1.327V     336.2mV
1.2ns     339.3mV    1.098V     191.7mV
1.4ns     240.2mV    917.7mV    182.2mV
1.8ns     201.9mV    421.9mV    174.9mV
2.2ns     196.9mV    276.8mV    173.5mV
10ns      194.2mV    251.3mV    172.6mV
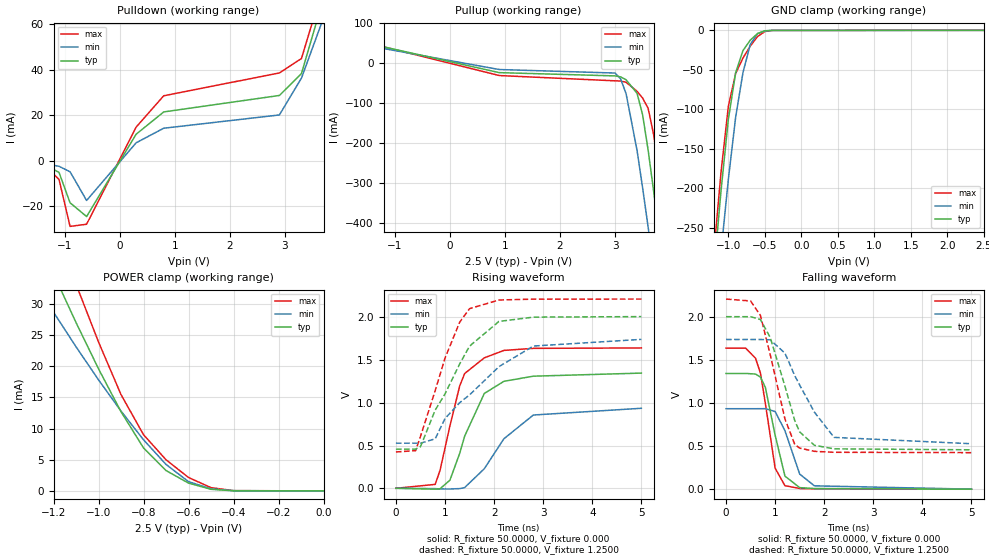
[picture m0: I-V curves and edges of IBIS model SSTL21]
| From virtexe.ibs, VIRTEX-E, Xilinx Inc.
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|   Model SSTL21
[Model]   SSTL21
Model_type   I/O
Polarity   Non-Inverting
Enable   Active-Low
Vinl =   1.070V
Vinh =   1.430V
Vmeas =   1.2500V
Cref =  30.0000pF
| The Rref below represents only the parallel load, there is actually a series
| R, see the application notes for details.
Rref =  50.0000
Vref =   1.2500V
C_comp   5.0000pF   4.0000pF   6.0000pF
[Temperature Range]   25.0000   100.0000   0.000
[Voltage Range]   2.5000V   2.3750V   2.6250V
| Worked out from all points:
|   slope of the pulldown table from 0 to 0.375 V, typ, clamps not added: 27.3 ohm
|   slope of the pullup table from 0 to 0.375 V, typ, clamps not added: 31.5 ohm
|   GND clamp passes 1 mA (typ) near -0.51 V on its own axis
|   POWER clamp passes 1 mA (typ) near -0.57 V on its own axis
|   rising waveform, R_fixture 50.0000, V_fixture 0.000: 20-80 % time 549ps typ, 760ps min, 435ps max; typ from 0 V to 1.35 V
|   rising waveform, R_fixture 50.0000, V_fixture 1.2500: 20-80 % time 852ps typ, 1.3ns min, 655ps max; typ from 0.457 V to 2.01 V
|   falling waveform, R_fixture 50.0000, V_fixture 0.000: 20-80 % time 293ps typ, 339ps min, 265ps max; typ from 1.35 V to 0 V
|   falling waveform, R_fixture 50.0000, V_fixture 1.2500: 20-80 % time 486ps typ, 654ps min, 439ps max; typ from 2.01 V to 0.458 V
[Pulldown]
| voltage   I(typ)   I(min)   I(max)
-2.5V     -1mA       -1mA       0A
-1.3V     -2.6mA     -1.6mA     -3.5mA
-1.1V     -5.2mA     -2.5mA     -8.3mA
-900mV    -18.52mA   -4.9mA     -28.89mA
-600mV    -24.57mA   -17.5mA    -27.95mA
300mV     11.6mA     7.84mA     14.73mA
800mV     21.38mA    14.22mA    28.48mA
2.9V      28.62mA    20.06mA    38.51mA
3.3V      38.23mA    36.23mA    44.84mA
3.7V      71.31mA    62.7mA     76.88mA
3.8V      81.06mA    70.06mA    88.33mA
5V        214.2mA    171.6mA    245.6mA
[Pullup]
| voltage   I(typ)   I(min)   I(max)
-2.5V     80.7mA     69mA       85.3mA
900mV     -23.61mA   -15.84mA   -30.89mA
3V        -31.76mA   -24.6mA    -44.07mA
3.1V      -34.16mA   -39.04mA   -44.56mA
3.2V      -41.41mA   -76.04mA   -47.65mA
3.4V      -75.41mA   -218.6mA   -70.39mA
3.5V      -128.9mA   -311.5mA   -86.99mA
3.6V      -216.9mA   -409.2mA   -112.6mA
3.7V      -319.5mA   -509.5mA   -178.3mA
3.8V      -427.9mA   -611.4mA   -276.3mA
4V        -652.2mA   -818.3mA   -498.8mA
5V        -1.816A    -1.877A    -1.694A
[GND_clamp]
| voltage   I(typ)   I(min)   I(max)
-2.5V     -1.803A    -1.736A    -1.828A
-1.2V     -306mA     -377.1mA   -282.7mA
-1.1V     -202.5mA   -280mA     -178.8mA
-1V       -112.5mA   -188.5mA   -95.98mA
-900mV    -53.49mA   -109.7mA   -54.53mA
-800mV    -25.67mA   -53.59mA   -35.13mA
-700mV    -12.44mA   -17.88mA   -19.82mA
-600mV    -3.982mA   -4.201mA   -7.865mA
-500mV    -601.5uA   -800.3uA   -1.508mA
-400mV    -51.05uA   -119.3uA   -124.3uA
2.5V      14.09nA    54.02nA    14.26nA
[POWER_clamp]
| voltage   I(typ)   I(min)   I(max)
-2.5V     147.4mA    107.9mA    181.9mA
-1.3V     42.9mA     34.4mA     52.99mA
-1.2V     34.81mA    28.66mA    42.89mA
-1.1V     27mA       23.11mA    33.14mA
-1V       19.58mA    17.81mA    23.88mA
-900mV    12.7mA     12.8mA     15.44mA
-800mV    6.896mA    8.202mA    9.016mA
-700mV    3.268mA    4.248mA    4.998mA
-600mV    1.254mA    1.488mA    2.15mA
-500mV    261.8uA    331.4uA    525.9uA
-400mV    22.44uA    43.93uA    49.08uA
0V        14.09nA    30.38nA    15.37nA
[Ramp]
| variable   typ   min   max
dV/dt_r   0.8076/0.5433n   0.5610/0.7569n   0.9840/0.4369n
dV/dt_f   0.7320/0.7982n   0.5154/1.0512n   0.9384/0.6768n
R_load = 50.0000
[Rising Waveform]
R_fixture = 50.0000
V_fixture = 0.000
| time   V(typ)   V(min)   V(max)
0s        2.227uV    0V         2.074uV
800ps     -10.17mV   -3.74mV    45.8mV
900ps     -5.115mV   -7.521mV   212.1mV
1.1ns     95.01mV    -8.513mV   729mV
1.3ns     409.9mV    -3.477mV   1.197V
1.4ns     608.7mV    8.37mV     1.341V
1.8ns     1.108V     228.3mV    1.524V
2.2ns     1.25V      579.1mV    1.611V
2.8ns     1.31V      856.2mV    1.635V
5ns       1.346V     935mV      1.64V
[Rising Waveform]
R_fixture = 50.0000
V_fixture = 1.2500
V_fixture_min = 1.1100
V_fixture_max = 1.3900
| time   V(typ)   V(min)   V(max)
0s        457.4mV    527.1mV    424.6mV
400ps     457.7mV    527.3mV    439.7mV
500ps     486mV      527.2mV    605.8mV
800ps     913mV      577.8mV    1.141V
1ns       1.103V     815mV      1.521V
1.3ns     1.454V     1.001V     1.942V
1.5ns     1.661V     1.091V     2.099V
2.1ns     1.95V      1.422V     2.2V
2.8ns     2V         1.662V     2.21V
5ns       2.006V     1.74V      2.211V
[Falling Waveform]
R_fixture = 50.0000
V_fixture = 0.000
| time   V(typ)   V(min)   V(max)
0s        1.346V     935.9mV    1.64V
400ps     1.346V     935.9mV    1.64V
600ps     1.339V     935.9mV    1.523V
700ps     1.304V     936.1mV    1.351V
800ps     1.186V     936.3mV    1.002V
1ns       628.4mV    903.4mV    244mV
1.2ns     151.7mV    680.2mV    40.59mV
1.5ns     18.26mV    176mV      8.492mV
1.8ns     7.562mV    39.15mV    4.233mV
5ns       432.5uV    494.9uV    322uV
[Falling Waveform]
R_fixture = 50.0000
V_fixture = 1.2500
V_fixture_min = 1.1100
V_fixture_max = 1.3900
| time   V(typ)   V(min)   V(max)
0s        2.006V     1.741V     2.211V
500ps     2.006V     1.741V     2.189V
700ps     1.973V     1.741V     2.021V
900ps     1.764V     1.737V     1.564V
1.2ns     1.198V     1.582V     816.5mV
1.4ns     797.6mV    1.32V      520.9mV
1.5ns     666mV      1.211V     477.7mV
1.8ns     510.7mV    895.8mV    440.3mV
2.2ns     469.1mV    602.5mV    429.2mV
5ns       458.2mV    528.7mV    425.2mV
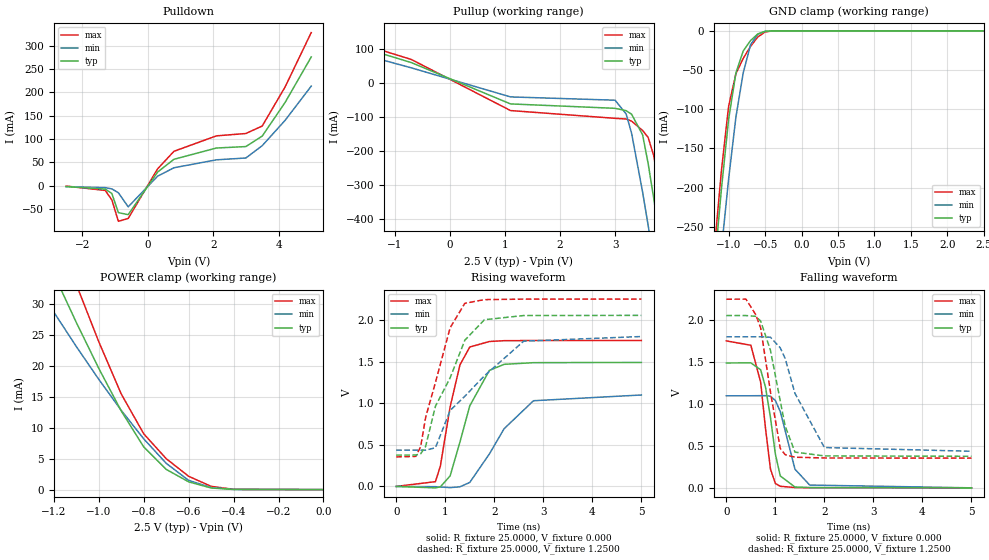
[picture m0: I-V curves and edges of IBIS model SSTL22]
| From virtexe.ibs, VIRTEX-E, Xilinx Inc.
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|   Model SSTL22
[Model]   SSTL22
Model_type   I/O
Polarity   Non-Inverting
Enable   Active-Low
Vinl =   1.070V
Vinh =   1.430V
Vmeas =   1.2500V
Cref =  30.0000pF
| The Rref below represents only the parallel load, there is actually a series
| R, see the application notes for details.
Rref =  25.0000
Vref =   1.2500V
C_comp   5.0000pF   4.0000pF   6.0000pF
[Temperature Range]   25.0000   100.0000   0.000
[Voltage Range]   2.5000V   2.3750V   2.6250V
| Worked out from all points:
|   slope of the pulldown table from 0 to 0.375 V, typ, clamps not added: 10.8 ohm
|   slope of the pullup table from 0 to 0.375 V, typ, clamps not added: 13.6 ohm
|   GND clamp passes 1 mA (typ) near -0.51 V on its own axis
|   POWER clamp passes 1 mA (typ) near -0.57 V on its own axis
|   rising waveform, R_fixture 25.0000, V_fixture 0.000: 20-80 % time 467ps typ, 725ps min, 343ps max; typ from 0 V to 1.49 V
|   rising waveform, R_fixture 25.0000, V_fixture 1.2500: 20-80 % time 667ps typ, 1.08ns min, 509ps max; typ from 0.376 V to 2.05 V
|   falling waveform, R_fixture 25.0000, V_fixture 0.000: 20-80 % time 239ps typ, 286ps min, 227ps max; typ from 1.49 V to 0 V
|   falling waveform, R_fixture 25.0000, V_fixture 1.2500: 20-80 % time 348ps typ, 485ps min, 289ps max; typ from 2.05 V to 0.376 V
[Pulldown]
| voltage   I(typ)   I(min)   I(max)
-2.5V     -2mA       -2mA       -1mA
-1.3V     -7.5mA     -4.4mA     -10.4mA
-1.1V     -16.8mA    -7mA       -30.6mA
-900mV    -57.91mA   -15.3mA    -76.47mA
-600mV    -62.21mA   -45.46mA   -70.39mA
300mV     29.12mA    20.23mA    36mA
800mV     56.47mA    38.3mA     73.59mA
2.1V      80.63mA    55.31mA    106.7mA
3V        83.7mA     59.24mA    111.7mA
3.5V      106.2mA    85.59mA    127.8mA
4.2V      178.3mA    139.9mA    211.5mA
5V        275.8mA    213.3mA    328.1mA
[Pullup]
| voltage   I(typ)   I(min)   I(max)
-2.5V     148.1mA    123.2mA    158.8mA
-700mV    59.19mA    43.75mA    68.37mA
1.1V      -62.36mA   -41.73mA   -81.95mA
3V        -75.36mA   -51.4mA    -104.8mA
3.2V      -82.3mA    -91.8mA    -106.8mA
3.3V      -92.74mA   -149mA     -113.1mA
3.5V      -153.5mA   -322.4mA   -140.6mA
3.6V      -237.5mA   -419.7mA   -161mA
3.7V      -338.6mA   -519.8mA   -213.6mA
3.8V      -446.3mA   -621.6mA   -305.8mA
4V        -670.1mA   -828.4mA   -525.3mA
5V        -1.834A    -1.888A    -1.72A
[GND_clamp]
| voltage   I(typ)   I(min)   I(max)
-2.5V     -1.803A    -1.736A    -1.828A
-1.2V     -306mA     -377.1mA   -282.7mA
-1.1V     -202.5mA   -280mA     -178.8mA
-1V       -112.5mA   -188.5mA   -95.98mA
-900mV    -53.49mA   -109.7mA   -54.53mA
-800mV    -25.67mA   -53.59mA   -35.13mA
-700mV    -12.44mA   -17.88mA   -19.82mA
-600mV    -3.982mA   -4.201mA   -7.865mA
-500mV    -601.5uA   -800.3uA   -1.508mA
-400mV    -51.05uA   -119.3uA   -124.3uA
2.5V      14.09nA    54.02nA    14.26nA
[POWER_clamp]
| voltage   I(typ)   I(min)   I(max)
-2.5V     147.4mA    107.9mA    181.9mA
-1.3V     42.9mA     34.4mA     52.99mA
-1.2V     34.81mA    28.66mA    42.89mA
-1.1V     27mA       23.11mA    33.14mA
-1V       19.58mA    17.81mA    23.88mA
-900mV    12.7mA     12.8mA     15.44mA
-800mV    6.896mA    8.202mA    9.016mA
-700mV    3.268mA    4.248mA    4.998mA
-600mV    1.254mA    1.488mA    2.15mA
-500mV    261.8uA    331.4uA    525.9uA
-400mV    22.44uA    43.93uA    49.08uA
0V        14.09nA    30.38nA    15.37nA
[Ramp]
| variable   typ   min   max
dV/dt_r   0.8934/0.4629n   0.6588/0.7209n   1.0512/0.3357n
dV/dt_f   0.9155/0.5388n   0.6798/0.8195n   1.0986/0.4093n
R_load = 25.0000
[Rising Waveform]
R_fixture = 25.0000
V_fixture = 0.000
| time   V(typ)   V(min)   V(max)
0s        1.125uV    0V         1.082uV
800ps     -17.18mV   -3.061mV   57.2mV
900ps     -5.248mV   -6.691mV   242.9mV
1.1ns     127.1mV    -14.42mV   956mV
1.3ns     533.5mV    -4.67mV    1.459V
1.5ns     967.4mV    47.92mV    1.674V
1.9ns     1.393V     389.6mV    1.74V
2.2ns     1.466V     692.7mV    1.75V
2.8ns     1.486V     1.029V     1.752V
5ns       1.489V     1.098V     1.752V
[Rising Waveform]
R_fixture = 25.0000
V_fixture = 1.2500
V_fixture_min = 1.1100
V_fixture_max = 1.3900
| time   V(typ)   V(min)   V(max)
0s        376.3mV    435.7mV    354.5mV
400ps     377mV      436mV      360.6mV
500ps     392.5mV    436mV      479.5mV
600ps     480.6mV    435.3mV    829.2mV
800ps     962.7mV    464.4mV    1.247V
1.1ns     1.304V     912mV      1.905V
1.4ns     1.756V     1.083V     2.199V
1.8ns     2.002V     1.329V     2.243V
2.6ns     2.052V     1.744V     2.249V
5ns       2.054V     1.8V       2.249V
[Falling Waveform]
R_fixture = 25.0000
V_fixture = 0.000
| time   V(typ)   V(min)   V(max)
0s        1.489V     1.098V     1.752V
500ps     1.49V      1.098V     1.7V
700ps     1.408V     1.099V     1.26V
800ps     1.198V     1.099V     703.4mV
900ps     838.8mV    1.093V     224.7mV
1ns       403.5mV    1.042V     52.78mV
1.1ns     142.2mV    910.3mV    18.69mV
1.4ns     9.826mV    222.3mV    3.94mV
1.7ns     3.755mV    33.52mV    1.88mV
5ns       183.5uV    339.8uV    128.7uV
[Falling Waveform]
R_fixture = 25.0000
V_fixture = 1.2500
V_fixture_min = 1.1100
V_fixture_max = 1.3900
| time   V(typ)   V(min)   V(max)
0s        2.054V     1.801V     2.249V
400ps     2.054V     1.801V     2.25V
600ps     2.045V     1.801V     2.065V
700ps     1.988V     1.801V     1.907V
900ps     1.641V     1.796V     1.144V
1.1ns     1.035V     1.669V     470.6mV
1.2ns     736.8mV    1.542V     396mV
1.4ns     426.3mV    1.126V     365.4mV
2ns       380.9mV    480.7mV    356.3mV
5ns       376.5mV    436.2mV    354.7mV
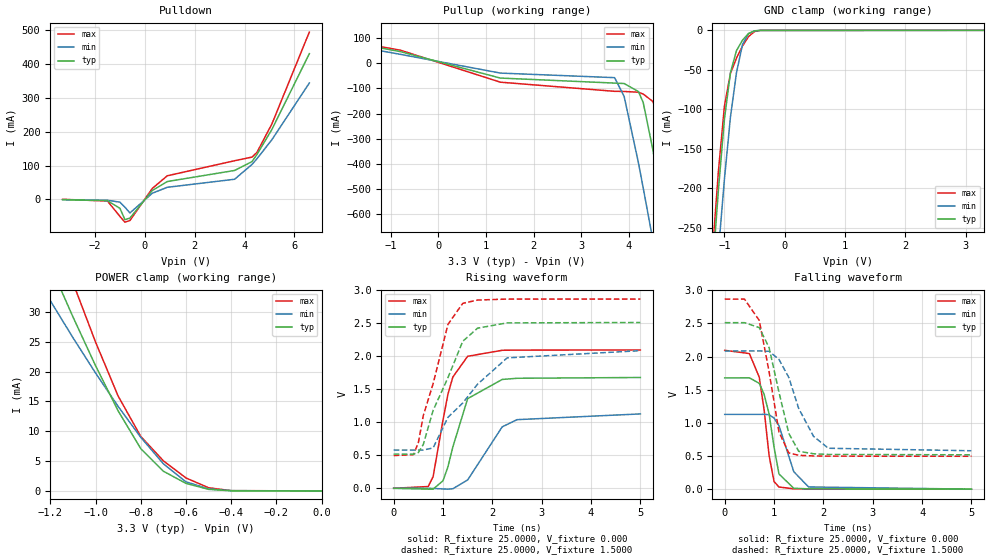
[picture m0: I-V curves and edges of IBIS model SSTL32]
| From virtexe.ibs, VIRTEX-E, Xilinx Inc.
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|   Model SSTL32
[Model]   SSTL32
Model_type   I/O
Polarity   Non-Inverting
Enable   Active-Low
Vinl =   1.300V
Vinh =   1.700V
Vmeas =   1.5000V
Cref =  30.0000pF
| The Rref below represents only the parallel load, there is actually a series
| R, see the application notes for details.
Rref =  25.0000
Vref =   1.5000V
C_comp   5.0000pF   4.0000pF   6.0000pF
[Temperature Range]   25.0000   100.0000   0.000
[Voltage Range]   3.3000V   3.0000V   3.6000V
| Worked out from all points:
|   slope of the pulldown table from 0 to 0.495 V, typ, clamps not added: 13 ohm
|   slope of the pullup table from 0 to 0.495 V, typ, clamps not added: 18.4 ohm
|   GND clamp passes 1 mA (typ) near -0.51 V on its own axis
|   POWER clamp passes 1 mA (typ) near -0.57 V on its own axis
|   rising waveform, R_fixture 25.0000, V_fixture 0.000: 20-80 % time 388ps typ, 570ps min, 334ps max; typ from 0 V to 1.68 V
|   rising waveform, R_fixture 25.0000, V_fixture 1.5000: 20-80 % time 635ps typ, 988ps min, 496ps max; typ from 0.518 V to 2.51 V
|   falling waveform, R_fixture 25.0000, V_fixture 0.000: 20-80 % time 244ps typ, 293ps min, 220ps max; typ from 1.68 V to 0 V
|   falling waveform, R_fixture 25.0000, V_fixture 1.5000: 20-80 % time 367ps typ, 505ps min, 321ps max; typ from 2.51 V to 0.518 V
[Pulldown]
| voltage   I(typ)   I(min)   I(max)
-3.3V     -1mA       -1mA       0A
-1.5V     -4.1mA     -2.8mA     -5.1mA
-1V       -26.7mA    -8.4mA     -50.62mA
-800mV    -60.15mA   -23.23mA   -67.67mA
-600mV    -55.46mA   -40.41mA   -62.76mA
300mV     26mA       18mA       32.25mA
900mV     52.59mA    35.53mA    69.58mA
3.6V      85.3mA     59.32mA    114.1mA
4.3V      111.5mA    103.1mA    124.9mA
4.5V      132.9mA    120.1mA    139mA
5.1V      207mA      176.5mA    223.3mA
6.6V      430.7mA    344mA      494.6mA
[Pullup]
| voltage   I(typ)   I(min)   I(max)
-3.3V     133.7mA    120.5mA    135.2mA
-800mV    45.72mA    34.98mA    51.5mA
1.3V      -59.14mA   -39.39mA   -75.47mA
3.7V      -79.07mA   -57.5mA    -111.7mA
3.9V      -80.75mA   -131.9mA   -112.3mA
4.2V      -112.6mA   -394.9mA   -115.2mA
4.3V      -155.6mA   -494.4mA   -122.6mA
4.5V      -340mA     -698.5mA   -151.4mA
4.7V      -558.4mA   -906.4mA   -238.3mA
4.9V      -785.2mA   -1.116A    -443.3mA
5.1V      -1.015A    -1.328A    -672.4mA
6.6V      -2.781A    -2.935A    -2.484A
[GND_clamp]
| voltage   I(typ)   I(min)   I(max)
-3.3V     -2.749A    -2.594A    -2.805A
-1.2V     -306mA     -377.1mA   -282.7mA
-1.1V     -202.5mA   -280mA     -178.8mA
-1V       -112.5mA   -188.5mA   -95.98mA
-900mV    -53.5mA    -109.7mA   -54.53mA
-800mV    -25.67mA   -53.59mA   -35.13mA
-700mV    -12.44mA   -17.88mA   -19.82mA
-600mV    -3.982mA   -4.202mA   -7.865mA
-500mV    -601.5uA   -800.3uA   -1.508mA
-400mV    -51.05uA   -119.3uA   -124.3uA
3.3V      18.74nA    3.634uA    18.92nA
[POWER_clamp]
| voltage   I(typ)   I(min)   I(max)
-3.3V     237mA      175.9mA    284.4mA
-1.3V     46.69mA    38.29mA    56.33mA
-1.2V     37.79mA    31.9mA     45.45mA
-1.1V     29.2mA     25.71mA    34.95mA
-1V       21.01mA    19.78mA    24.97mA
-900mV    13.43mA    14.17mA    15.91mA
-800mV    7.091mA    8.993mA    9.139mA
-700mV    3.305mA    4.554mA    5.052mA
-600mV    1.265mA    1.529mA    2.172mA
-500mV    263.8uA    333.6uA    531.5uA
-400mV    22.63uA    44.12uA    49.77uA
0V        18.8nA     38.3nA     22.53nA
[Ramp]
| variable   typ   min   max
dV/dt_r   1.0074/0.4112n   0.6762/0.6074n   1.2570/0.3249n
dV/dt_f   0.9858/0.5546n   0.7110/0.8578n   1.2558/0.4368n
R_load = 25.0000
[Rising Waveform]
R_fixture = 25.0000
V_fixture = 0.000
| time   V(typ)   V(min)   V(max)
0s        1.551uV    1.726uV    1.533uV
700ps     -13.06mV   57.6uV     26.94mV
800ps     -12.81mV   -2.273mV   177mV
1ns       113.7mV    -9.905mV   1.033V
1.1ns     325.3mV    -13.11mV   1.425V
1.2ns     627.8mV    -6.25mV    1.687V
1.5ns     1.359V     126.7mV    2V
2.2ns     1.649V     931.1mV    2.091V
2.5ns     1.667V     1.04V      2.094V
5ns       1.679V     1.127V     2.095V
[Rising Waveform]
R_fixture = 25.0000
V_fixture = 1.5000
V_fixture_min = 1.3000
V_fixture_max = 1.7000
| time   V(typ)   V(min)   V(max)
0s        518.1mV    579.1mV    496.3mV
400ps     517.8mV    579.2mV    508.6mV
500ps     540.9mV    579.2mV    689.3mV
600ps     662.5mV    579.1mV    1.099V
800ps     1.181V     612.5mV    1.585V
1.1ns     1.675V     1.075V     2.483V
1.4ns     2.227V     1.292V     2.802V
1.7ns     2.426V     1.577V     2.852V
2.3ns     2.506V     1.976V     2.867V
5ns       2.512V     2.085V     2.867V
[Falling Waveform]
R_fixture = 25.0000
V_fixture = 0.000
| time   V(typ)   V(min)   V(max)
0s        1.679V     1.128V     2.095V
500ps     1.68V      1.128V     2.046V
700ps     1.597V     1.128V     1.69V
800ps     1.429V     1.129V     1.191V
900ps     1.135V     1.123V     506.8mV
1ns       634.5mV    1.073V     115.7mV
1.1ns     229.5mV    958.2mV    32.4mV
1.4ns     13.28mV    263.7mV    5.301mV
1.7ns     4.906mV    33.58mV    2.253mV
5ns       185.8uV    313.8uV    152uV
[Falling Waveform]
R_fixture = 25.0000
V_fixture = 1.5000
V_fixture_min = 1.3000
V_fixture_max = 1.7000
| time   V(typ)   V(min)   V(max)
0s        2.512V     2.085V     2.867V
400ps     2.512V     2.085V     2.868V
700ps     2.438V     2.086V     2.546V
900ps     2.136V     2.08V      1.771V
1.1ns     1.462V     1.958V     861.3mV
1.3ns     841mV      1.684V     545.8mV
1.5ns     570.7mV    1.217V     511.3mV
1.8ns     534.4mV    797.7mV    501.1mV
2.1ns     523.8mV    617.3mV    498.3mV
5ns       518.5mV    579.7mV    496.5mV
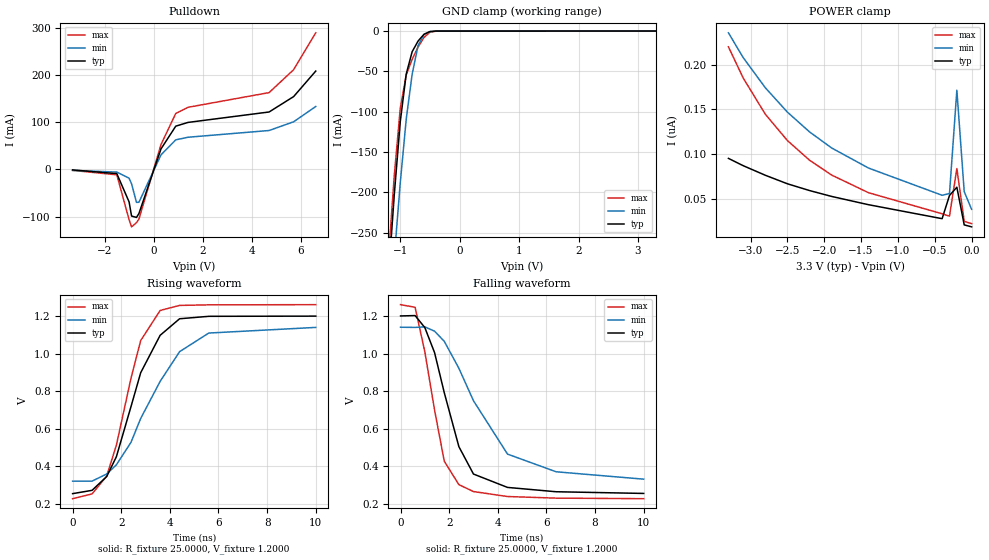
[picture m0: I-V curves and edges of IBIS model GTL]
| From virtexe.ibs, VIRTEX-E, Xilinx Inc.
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|   Model GTL
[Model]   GTL
Model_type   I/O_open_drain
Polarity   Non-Inverting
Enable   Active-Low
Vinl =   0.750V
Vinh =   0.850V
Vmeas =   0.8000V
Cref =  0.000F
Rref =  25.0000
Vref =   1.2000V
C_comp   5.0000pF   4.0000pF   6.0000pF
[Temperature Range]   25.0000   100.0000   0.000
[Voltage Range]   3.3000V   3.0000V   3.6000V
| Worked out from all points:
|   slope of the pulldown table from 0 to 0.495 V, typ, clamps not added: 7.61 ohm
|   GND clamp passes 1 mA (typ) near -0.51 V on its own axis
|   rising waveform, R_fixture 25.0000, V_fixture 1.2000: 20-80 % time 1.44ns typ, 1.99ns min, 1.13ns max; typ from 0.255 V to 1.2 V
|   falling waveform, R_fixture 25.0000, V_fixture 1.2000: 20-80 % time 1.2ns typ, 2.03ns min, 854ps max; typ from 1.2 V to 0.256 V
[Pulldown]
| voltage   I(typ)   I(min)   I(max)
-3.3V     -1mA       -2mA       -2mA
-1.5V     -8.9mA     -5.6mA     -11.4mA
-1V       -68.7mA    -18.6mA    -106.4mA
-900mV    -98.6mA    -30.3mA    -121.5mA
-700mV    -101.6mA   -69.62mA   -112.7mA
-600mV    -93.33mA   -69.52mA   -105.1mA
300mV     43.58mA    30.95mA    52.82mA
900mV     91.59mA    62.65mA    118.5mA
1.4V      99.52mA    68.15mA    131.5mA
4.7V      121.6mA    82.39mA    162.6mA
5.7V      154.2mA    100.9mA    211.1mA
6.6V      208.2mA    133.2mA    289.1mA
[GND_clamp]
| voltage   I(typ)   I(min)   I(max)
-3.3V     -2.749A    -2.594A    -2.804A
-1.2V     -306mA     -377.1mA   -282.7mA
-1.1V     -202.5mA   -280mA     -178.8mA
-1V       -112.5mA   -188.5mA   -95.98mA
-900mV    -53.5mA    -109.7mA   -54.53mA
-800mV    -25.67mA   -53.6mA    -35.13mA
-700mV    -12.44mA   -17.88mA   -19.82mA
-600mV    -3.982mA   -4.204mA   -7.866mA
-500mV    -601.6uA   -801.1uA   -1.508mA
-400mV    -51.05uA   -119.5uA   -124.3uA
3.3V      18.57nA    1.016uA    17.75nA
[POWER_clamp]
| voltage   I(typ)   I(min)   I(max)
-3.3V     95.11nA    235.6nA    219.9nA
-3.1V     86.96nA    207.9nA    185.1nA
-2.8V     76.25nA    174.2nA    144.6nA
-2.5V     66.71nA    146.9nA    115.1nA
-2.2V     59.14nA    124.8nA    93.13nA
-1.9V     52.56nA    106.8nA    76.48nA
-1.4V     43.31nA    84.34nA    56.75nA
-400mV    27.65nA    53.84nA    33.12nA
-300mV    53.61nA    55.76nA    30.5nA
-200mV    62.86nA    171.4nA    83.76nA
-100mV    20.72nA    57.86nA    24.62nA
0V        18.51nA    38.13nA    22.12nA
[Ramp]
| variable   typ   min   max
dV/dt_r   1.4006/1.7687n   1.0122/2.2985n   1.6768/1.5451n
dV/dt_f   1.3829/3.1009n   0.9354/3.9220n   1.6748/2.2829n
R_load = 25.0000
[Rising Waveform]
R_fixture = 25.0000
V_fixture = 1.2000
V_fixture_min = 1.1400
V_fixture_max = 1.2600
| time   V(typ)   V(min)   V(max)
0s        254.8mV    321.1mV    228mV
800ps     272.4mV    321.3mV    253.3mV
1.4ns     345.5mV    359.3mV    347.8mV
1.8ns     451.2mV    408.1mV    512.5mV
2.4ns     717.3mV    527.5mV    868.2mV
2.8ns     897.9mV    654.7mV    1.069V
3.6ns     1.097V     852mV      1.229V
4.4ns     1.185V     1.01V      1.256V
5.6ns     1.198V     1.109V     1.259V
10ns      1.199V     1.139V     1.26V
[Falling Waveform]
R_fixture = 25.0000
V_fixture = 1.2000
V_fixture_min = 1.1400
V_fixture_max = 1.2600
| time   V(typ)   V(min)   V(max)
0s        1.2V       1.14V      1.26V
600ps     1.202V     1.139V     1.246V
1ns       1.138V     1.142V     1.009V
1.4ns     1.005V     1.119V     699.9mV
1.8ns     791.6mV    1.065V     427.2mV
2.4ns     505mV      921.6mV    303mV
3ns       359.3mV    749.1mV    266.2mV
4.4ns     288.2mV    465.4mV    239.8mV
6.4ns     265.2mV    371.3mV    231.2mV
10ns      256.2mV    332.1mV    228.3mV
